VERSION 5.7 ;
  NOWIREEXTENSIONATPIN ON ;
  DIVIDERCHAR "/" ;
  BUSBITCHARS "[]" ;
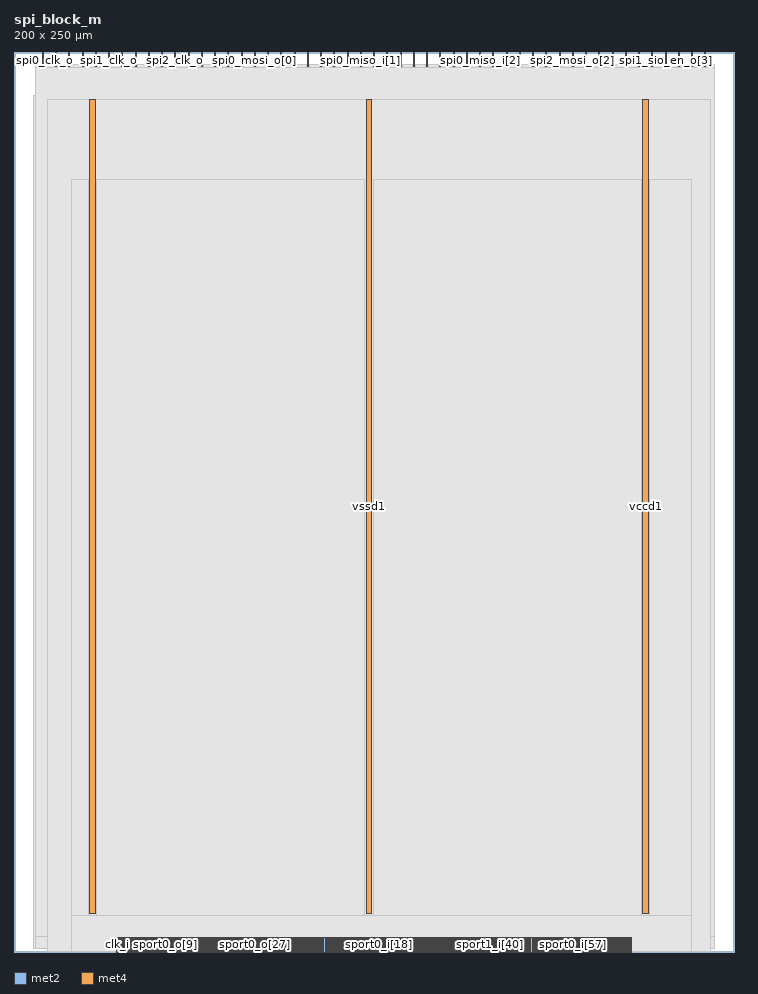
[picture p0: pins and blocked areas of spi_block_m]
MACRO spi_block_m
  CLASS BLOCK ;
  FOREIGN spi_block_m ;
  ORIGIN 0.000 0.000 ;
  SIZE 200.000 BY 250.000 ;
  PIN clk_i
    DIRECTION INPUT ;
    USE SIGNAL ;
    ANTENNAGATEAREA 0.852000 ;
    PORT
      LAYER met2 ;
        RECT 28.610 0.000 28.890 4.000 ;
    END
  END clk_i
  PIN nrst_i
    DIRECTION INPUT ;
    USE SIGNAL ;
    ANTENNAGATEAREA 0.196500 ;
    PORT
      LAYER met2 ;
        RECT 29.070 0.000 29.350 4.000 ;
    END
  END nrst_i
  PIN spi0_clk_o
    DIRECTION OUTPUT TRISTATE ;
    USE SIGNAL ;
    ANTENNADIFFAREA 0.795200 ;
    PORT
      LAYER met2 ;
        RECT 7.910 246.000 8.190 250.000 ;
    END
  END spi0_clk_o
  PIN spi0_cs_o
    DIRECTION OUTPUT TRISTATE ;
    USE SIGNAL ;
    ANTENNADIFFAREA 0.795200 ;
    PORT
      LAYER met2 ;
        RECT 11.590 246.000 11.870 250.000 ;
    END
  END spi0_cs_o
  PIN spi0_dqsm_en_o
    DIRECTION OUTPUT TRISTATE ;
    USE SIGNAL ;
    ANTENNADIFFAREA 0.795200 ;
    PORT
      LAYER met2 ;
        RECT 15.270 246.000 15.550 250.000 ;
    END
  END spi0_dqsm_en_o
  PIN spi0_dqsm_i
    DIRECTION INPUT ;
    USE SIGNAL ;
    ANTENNAGATEAREA 0.196500 ;
    PORT
      LAYER met2 ;
        RECT 18.950 246.000 19.230 250.000 ;
    END
  END spi0_dqsm_i
  PIN spi0_dqsm_o
    DIRECTION OUTPUT TRISTATE ;
    USE SIGNAL ;
    ANTENNADIFFAREA 0.795200 ;
    PORT
      LAYER met2 ;
        RECT 22.630 246.000 22.910 250.000 ;
    END
  END spi0_dqsm_o
  PIN spi0_miso_i[0]
    DIRECTION INPUT ;
    USE SIGNAL ;
    ANTENNAGATEAREA 0.196500 ;
    PORT
      LAYER met2 ;
        RECT 63.110 246.000 63.390 250.000 ;
    END
  END spi0_miso_i[0]
  PIN spi0_miso_i[1]
    DIRECTION INPUT ;
    USE SIGNAL ;
    ANTENNAGATEAREA 0.196500 ;
    PORT
      LAYER met2 ;
        RECT 96.230 246.000 96.510 250.000 ;
    END
  END spi0_miso_i[1]
  PIN spi0_miso_i[2]
    DIRECTION INPUT ;
    USE SIGNAL ;
    ANTENNAGATEAREA 0.196500 ;
    PORT
      LAYER met2 ;
        RECT 129.350 246.000 129.630 250.000 ;
    END
  END spi0_miso_i[2]
  PIN spi0_miso_i[3]
    DIRECTION INPUT ;
    USE SIGNAL ;
    ANTENNAGATEAREA 0.196500 ;
    PORT
      LAYER met2 ;
        RECT 162.470 246.000 162.750 250.000 ;
    END
  END spi0_miso_i[3]
  PIN spi0_mosi_o[0]
    DIRECTION OUTPUT TRISTATE ;
    USE SIGNAL ;
    ANTENNADIFFAREA 0.795200 ;
    PORT
      LAYER met2 ;
        RECT 66.790 246.000 67.070 250.000 ;
    END
  END spi0_mosi_o[0]
  PIN spi0_mosi_o[1]
    DIRECTION OUTPUT TRISTATE ;
    USE SIGNAL ;
    ANTENNADIFFAREA 0.795200 ;
    PORT
      LAYER met2 ;
        RECT 99.910 246.000 100.190 250.000 ;
    END
  END spi0_mosi_o[1]
  PIN spi0_mosi_o[2]
    DIRECTION OUTPUT TRISTATE ;
    USE SIGNAL ;
    ANTENNADIFFAREA 0.795200 ;
    PORT
      LAYER met2 ;
        RECT 133.030 246.000 133.310 250.000 ;
    END
  END spi0_mosi_o[2]
  PIN spi0_mosi_o[3]
    DIRECTION OUTPUT TRISTATE ;
    USE SIGNAL ;
    ANTENNADIFFAREA 0.795200 ;
    PORT
      LAYER met2 ;
        RECT 166.150 246.000 166.430 250.000 ;
    END
  END spi0_mosi_o[3]
  PIN spi0_sio_en_o[0]
    DIRECTION OUTPUT TRISTATE ;
    USE SIGNAL ;
    ANTENNADIFFAREA 0.795200 ;
    PORT
      LAYER met2 ;
        RECT 70.470 246.000 70.750 250.000 ;
    END
  END spi0_sio_en_o[0]
  PIN spi0_sio_en_o[1]
    DIRECTION OUTPUT TRISTATE ;
    USE SIGNAL ;
    ANTENNADIFFAREA 0.795200 ;
    PORT
      LAYER met2 ;
        RECT 103.590 246.000 103.870 250.000 ;
    END
  END spi0_sio_en_o[1]
  PIN spi0_sio_en_o[2]
    DIRECTION OUTPUT TRISTATE ;
    USE SIGNAL ;
    ANTENNADIFFAREA 0.795200 ;
    PORT
      LAYER met2 ;
        RECT 136.710 246.000 136.990 250.000 ;
    END
  END spi0_sio_en_o[2]
  PIN spi0_sio_en_o[3]
    DIRECTION OUTPUT TRISTATE ;
    USE SIGNAL ;
    ANTENNADIFFAREA 0.795200 ;
    PORT
      LAYER met2 ;
        RECT 169.830 246.000 170.110 250.000 ;
    END
  END spi0_sio_en_o[3]
  PIN spi1_clk_o
    DIRECTION OUTPUT TRISTATE ;
    USE SIGNAL ;
    ANTENNADIFFAREA 0.795200 ;
    PORT
      LAYER met2 ;
        RECT 26.310 246.000 26.590 250.000 ;
    END
  END spi1_clk_o
  PIN spi1_cs_o
    DIRECTION OUTPUT TRISTATE ;
    USE SIGNAL ;
    ANTENNADIFFAREA 0.795200 ;
    PORT
      LAYER met2 ;
        RECT 29.990 246.000 30.270 250.000 ;
    END
  END spi1_cs_o
  PIN spi1_dqsm_en_o
    DIRECTION OUTPUT TRISTATE ;
    USE SIGNAL ;
    ANTENNADIFFAREA 0.795200 ;
    PORT
      LAYER met2 ;
        RECT 33.670 246.000 33.950 250.000 ;
    END
  END spi1_dqsm_en_o
  PIN spi1_dqsm_i
    DIRECTION INPUT ;
    USE SIGNAL ;
    ANTENNAGATEAREA 0.196500 ;
    PORT
      LAYER met2 ;
        RECT 37.350 246.000 37.630 250.000 ;
    END
  END spi1_dqsm_i
  PIN spi1_dqsm_o
    DIRECTION OUTPUT TRISTATE ;
    USE SIGNAL ;
    ANTENNADIFFAREA 0.795200 ;
    PORT
      LAYER met2 ;
        RECT 41.030 246.000 41.310 250.000 ;
    END
  END spi1_dqsm_o
  PIN spi1_miso_i[0]
    DIRECTION INPUT ;
    USE SIGNAL ;
    ANTENNAGATEAREA 0.196500 ;
    PORT
      LAYER met2 ;
        RECT 74.150 246.000 74.430 250.000 ;
    END
  END spi1_miso_i[0]
  PIN spi1_miso_i[1]
    DIRECTION INPUT ;
    USE SIGNAL ;
    ANTENNAGATEAREA 0.196500 ;
    PORT
      LAYER met2 ;
        RECT 107.270 246.000 107.550 250.000 ;
    END
  END spi1_miso_i[1]
  PIN spi1_miso_i[2]
    DIRECTION INPUT ;
    USE SIGNAL ;
    ANTENNAGATEAREA 0.196500 ;
    PORT
      LAYER met2 ;
        RECT 140.390 246.000 140.670 250.000 ;
    END
  END spi1_miso_i[2]
  PIN spi1_miso_i[3]
    DIRECTION INPUT ;
    USE SIGNAL ;
    ANTENNAGATEAREA 0.196500 ;
    PORT
      LAYER met2 ;
        RECT 173.510 246.000 173.790 250.000 ;
    END
  END spi1_miso_i[3]
  PIN spi1_mosi_o[0]
    DIRECTION OUTPUT TRISTATE ;
    USE SIGNAL ;
    ANTENNADIFFAREA 0.795200 ;
    PORT
      LAYER met2 ;
        RECT 77.830 246.000 78.110 250.000 ;
    END
  END spi1_mosi_o[0]
  PIN spi1_mosi_o[1]
    DIRECTION OUTPUT TRISTATE ;
    USE SIGNAL ;
    ANTENNADIFFAREA 0.795200 ;
    PORT
      LAYER met2 ;
        RECT 110.950 246.000 111.230 250.000 ;
    END
  END spi1_mosi_o[1]
  PIN spi1_mosi_o[2]
    DIRECTION OUTPUT TRISTATE ;
    USE SIGNAL ;
    ANTENNADIFFAREA 0.795200 ;
    PORT
      LAYER met2 ;
        RECT 144.070 246.000 144.350 250.000 ;
    END
  END spi1_mosi_o[2]
  PIN spi1_mosi_o[3]
    DIRECTION OUTPUT TRISTATE ;
    USE SIGNAL ;
    ANTENNADIFFAREA 0.795200 ;
    PORT
      LAYER met2 ;
        RECT 177.190 246.000 177.470 250.000 ;
    END
  END spi1_mosi_o[3]
  PIN spi1_sio_en_o[0]
    DIRECTION OUTPUT TRISTATE ;
    USE SIGNAL ;
    ANTENNADIFFAREA 0.795200 ;
    PORT
      LAYER met2 ;
        RECT 81.510 246.000 81.790 250.000 ;
    END
  END spi1_sio_en_o[0]
  PIN spi1_sio_en_o[1]
    DIRECTION OUTPUT TRISTATE ;
    USE SIGNAL ;
    ANTENNADIFFAREA 0.795200 ;
    PORT
      LAYER met2 ;
        RECT 114.630 246.000 114.910 250.000 ;
    END
  END spi1_sio_en_o[1]
  PIN spi1_sio_en_o[2]
    DIRECTION OUTPUT TRISTATE ;
    USE SIGNAL ;
    ANTENNADIFFAREA 0.795200 ;
    PORT
      LAYER met2 ;
        RECT 147.750 246.000 148.030 250.000 ;
    END
  END spi1_sio_en_o[2]
  PIN spi1_sio_en_o[3]
    DIRECTION OUTPUT TRISTATE ;
    USE SIGNAL ;
    ANTENNADIFFAREA 0.795200 ;
    PORT
      LAYER met2 ;
        RECT 180.870 246.000 181.150 250.000 ;
    END
  END spi1_sio_en_o[3]
  PIN spi2_clk_o
    DIRECTION OUTPUT TRISTATE ;
    USE SIGNAL ;
    ANTENNADIFFAREA 0.795200 ;
    PORT
      LAYER met2 ;
        RECT 44.710 246.000 44.990 250.000 ;
    END
  END spi2_clk_o
  PIN spi2_cs_o
    DIRECTION OUTPUT TRISTATE ;
    USE SIGNAL ;
    ANTENNADIFFAREA 0.795200 ;
    PORT
      LAYER met2 ;
        RECT 48.390 246.000 48.670 250.000 ;
    END
  END spi2_cs_o
  PIN spi2_dqsm_en_o
    DIRECTION OUTPUT TRISTATE ;
    USE SIGNAL ;
    ANTENNADIFFAREA 0.795200 ;
    PORT
      LAYER met2 ;
        RECT 52.070 246.000 52.350 250.000 ;
    END
  END spi2_dqsm_en_o
  PIN spi2_dqsm_i
    DIRECTION INPUT ;
    USE SIGNAL ;
    ANTENNAGATEAREA 0.196500 ;
    PORT
      LAYER met2 ;
        RECT 55.750 246.000 56.030 250.000 ;
    END
  END spi2_dqsm_i
  PIN spi2_dqsm_o
    DIRECTION OUTPUT TRISTATE ;
    USE SIGNAL ;
    ANTENNADIFFAREA 0.795200 ;
    PORT
      LAYER met2 ;
        RECT 59.430 246.000 59.710 250.000 ;
    END
  END spi2_dqsm_o
  PIN spi2_miso_i[0]
    DIRECTION INPUT ;
    USE SIGNAL ;
    ANTENNAGATEAREA 0.196500 ;
    PORT
      LAYER met2 ;
        RECT 85.190 246.000 85.470 250.000 ;
    END
  END spi2_miso_i[0]
  PIN spi2_miso_i[1]
    DIRECTION INPUT ;
    USE SIGNAL ;
    ANTENNAGATEAREA 0.196500 ;
    PORT
      LAYER met2 ;
        RECT 118.310 246.000 118.590 250.000 ;
    END
  END spi2_miso_i[1]
  PIN spi2_miso_i[2]
    DIRECTION INPUT ;
    USE SIGNAL ;
    ANTENNAGATEAREA 0.196500 ;
    PORT
      LAYER met2 ;
        RECT 151.430 246.000 151.710 250.000 ;
    END
  END spi2_miso_i[2]
  PIN spi2_miso_i[3]
    DIRECTION INPUT ;
    USE SIGNAL ;
    ANTENNAGATEAREA 0.196500 ;
    PORT
      LAYER met2 ;
        RECT 184.550 246.000 184.830 250.000 ;
    END
  END spi2_miso_i[3]
  PIN spi2_mosi_o[0]
    DIRECTION OUTPUT TRISTATE ;
    USE SIGNAL ;
    ANTENNADIFFAREA 0.795200 ;
    PORT
      LAYER met2 ;
        RECT 88.870 246.000 89.150 250.000 ;
    END
  END spi2_mosi_o[0]
  PIN spi2_mosi_o[1]
    DIRECTION OUTPUT TRISTATE ;
    USE SIGNAL ;
    ANTENNADIFFAREA 0.795200 ;
    PORT
      LAYER met2 ;
        RECT 121.990 246.000 122.270 250.000 ;
    END
  END spi2_mosi_o[1]
  PIN spi2_mosi_o[2]
    DIRECTION OUTPUT TRISTATE ;
    USE SIGNAL ;
    ANTENNADIFFAREA 0.795200 ;
    PORT
      LAYER met2 ;
        RECT 155.110 246.000 155.390 250.000 ;
    END
  END spi2_mosi_o[2]
  PIN spi2_mosi_o[3]
    DIRECTION OUTPUT TRISTATE ;
    USE SIGNAL ;
    ANTENNADIFFAREA 0.795200 ;
    PORT
      LAYER met2 ;
        RECT 188.230 246.000 188.510 250.000 ;
    END
  END spi2_mosi_o[3]
  PIN spi2_sio_en_o[0]
    DIRECTION OUTPUT TRISTATE ;
    USE SIGNAL ;
    ANTENNADIFFAREA 0.795200 ;
    PORT
      LAYER met2 ;
        RECT 92.550 246.000 92.830 250.000 ;
    END
  END spi2_sio_en_o[0]
  PIN spi2_sio_en_o[1]
    DIRECTION OUTPUT TRISTATE ;
    USE SIGNAL ;
    ANTENNADIFFAREA 0.795200 ;
    PORT
      LAYER met2 ;
        RECT 125.670 246.000 125.950 250.000 ;
    END
  END spi2_sio_en_o[1]
  PIN spi2_sio_en_o[2]
    DIRECTION OUTPUT TRISTATE ;
    USE SIGNAL ;
    ANTENNADIFFAREA 0.795200 ;
    PORT
      LAYER met2 ;
        RECT 158.790 246.000 159.070 250.000 ;
    END
  END spi2_sio_en_o[2]
  PIN spi2_sio_en_o[3]
    DIRECTION OUTPUT TRISTATE ;
    USE SIGNAL ;
    ANTENNADIFFAREA 0.795200 ;
    PORT
      LAYER met2 ;
        RECT 191.910 246.000 192.190 250.000 ;
    END
  END spi2_sio_en_o[3]
  PIN sport0_i[0]
    DIRECTION INPUT ;
    USE SIGNAL ;
    ANTENNAGATEAREA 0.196500 ;
    PORT
      LAYER met2 ;
        RECT 76.450 0.000 76.730 4.000 ;
    END
  END sport0_i[0]
  PIN sport0_i[10]
    DIRECTION INPUT ;
    USE SIGNAL ;
    ANTENNAGATEAREA 0.196500 ;
    PORT
      LAYER met2 ;
        RECT 90.250 0.000 90.530 4.000 ;
    END
  END sport0_i[10]
  PIN sport0_i[11]
    DIRECTION INPUT ;
    USE SIGNAL ;
    ANTENNAGATEAREA 0.196500 ;
    PORT
      LAYER met2 ;
        RECT 91.630 0.000 91.910 4.000 ;
    END
  END sport0_i[11]
  PIN sport0_i[12]
    DIRECTION INPUT ;
    USE SIGNAL ;
    ANTENNAGATEAREA 0.196500 ;
    PORT
      LAYER met2 ;
        RECT 93.010 0.000 93.290 4.000 ;
    END
  END sport0_i[12]
  PIN sport0_i[13]
    DIRECTION INPUT ;
    USE SIGNAL ;
    ANTENNAGATEAREA 0.196500 ;
    PORT
      LAYER met2 ;
        RECT 94.390 0.000 94.670 4.000 ;
    END
  END sport0_i[13]
  PIN sport0_i[14]
    DIRECTION INPUT ;
    USE SIGNAL ;
    ANTENNAGATEAREA 0.196500 ;
    PORT
      LAYER met2 ;
        RECT 95.770 0.000 96.050 4.000 ;
    END
  END sport0_i[14]
  PIN sport0_i[15]
    DIRECTION INPUT ;
    USE SIGNAL ;
    ANTENNAGATEAREA 0.196500 ;
    PORT
      LAYER met2 ;
        RECT 97.150 0.000 97.430 4.000 ;
    END
  END sport0_i[15]
  PIN sport0_i[16]
    DIRECTION INPUT ;
    USE SIGNAL ;
    ANTENNAGATEAREA 0.196500 ;
    PORT
      LAYER met2 ;
        RECT 98.530 0.000 98.810 4.000 ;
    END
  END sport0_i[16]
  PIN sport0_i[17]
    DIRECTION INPUT ;
    USE SIGNAL ;
    ANTENNAGATEAREA 0.196500 ;
    PORT
      LAYER met2 ;
        RECT 99.910 0.000 100.190 4.000 ;
    END
  END sport0_i[17]
  PIN sport0_i[18]
    DIRECTION INPUT ;
    USE SIGNAL ;
    ANTENNAGATEAREA 0.196500 ;
    PORT
      LAYER met2 ;
        RECT 101.290 0.000 101.570 4.000 ;
    END
  END sport0_i[18]
  PIN sport0_i[19]
    DIRECTION INPUT ;
    USE SIGNAL ;
    ANTENNAGATEAREA 0.196500 ;
    PORT
      LAYER met2 ;
        RECT 102.670 0.000 102.950 4.000 ;
    END
  END sport0_i[19]
  PIN sport0_i[1]
    DIRECTION INPUT ;
    USE SIGNAL ;
    ANTENNAGATEAREA 0.196500 ;
    ANTENNADIFFAREA 0.434700 ;
    PORT
      LAYER met2 ;
        RECT 77.830 0.000 78.110 4.000 ;
    END
  END sport0_i[1]
  PIN sport0_i[20]
    DIRECTION INPUT ;
    USE SIGNAL ;
    ANTENNAGATEAREA 0.196500 ;
    PORT
      LAYER met2 ;
        RECT 104.050 0.000 104.330 4.000 ;
    END
  END sport0_i[20]
  PIN sport0_i[21]
    DIRECTION INPUT ;
    USE SIGNAL ;
    ANTENNAGATEAREA 0.196500 ;
    PORT
      LAYER met2 ;
        RECT 105.430 0.000 105.710 4.000 ;
    END
  END sport0_i[21]
  PIN sport0_i[22]
    DIRECTION INPUT ;
    USE SIGNAL ;
    ANTENNAGATEAREA 0.196500 ;
    PORT
      LAYER met2 ;
        RECT 106.810 0.000 107.090 4.000 ;
    END
  END sport0_i[22]
  PIN sport0_i[23]
    DIRECTION INPUT ;
    USE SIGNAL ;
    ANTENNAGATEAREA 0.196500 ;
    PORT
      LAYER met2 ;
        RECT 108.190 0.000 108.470 4.000 ;
    END
  END sport0_i[23]
  PIN sport0_i[24]
    DIRECTION INPUT ;
    USE SIGNAL ;
    ANTENNAGATEAREA 0.196500 ;
    PORT
      LAYER met2 ;
        RECT 109.570 0.000 109.850 4.000 ;
    END
  END sport0_i[24]
  PIN sport0_i[25]
    DIRECTION INPUT ;
    USE SIGNAL ;
    ANTENNAGATEAREA 0.196500 ;
    PORT
      LAYER met2 ;
        RECT 110.950 0.000 111.230 4.000 ;
    END
  END sport0_i[25]
  PIN sport0_i[26]
    DIRECTION INPUT ;
    USE SIGNAL ;
    ANTENNAGATEAREA 0.196500 ;
    PORT
      LAYER met2 ;
        RECT 112.330 0.000 112.610 4.000 ;
    END
  END sport0_i[26]
  PIN sport0_i[27]
    DIRECTION INPUT ;
    USE SIGNAL ;
    ANTENNAGATEAREA 0.196500 ;
    PORT
      LAYER met2 ;
        RECT 113.710 0.000 113.990 4.000 ;
    END
  END sport0_i[27]
  PIN sport0_i[28]
    DIRECTION INPUT ;
    USE SIGNAL ;
    ANTENNAGATEAREA 0.196500 ;
    PORT
      LAYER met2 ;
        RECT 115.090 0.000 115.370 4.000 ;
    END
  END sport0_i[28]
  PIN sport0_i[29]
    DIRECTION INPUT ;
    USE SIGNAL ;
    ANTENNAGATEAREA 0.196500 ;
    PORT
      LAYER met2 ;
        RECT 116.470 0.000 116.750 4.000 ;
    END
  END sport0_i[29]
  PIN sport0_i[2]
    DIRECTION INPUT ;
    USE SIGNAL ;
    ANTENNAGATEAREA 0.196500 ;
    PORT
      LAYER met2 ;
        RECT 79.210 0.000 79.490 4.000 ;
    END
  END sport0_i[2]
  PIN sport0_i[30]
    DIRECTION INPUT ;
    USE SIGNAL ;
    ANTENNAGATEAREA 0.196500 ;
    PORT
      LAYER met2 ;
        RECT 117.850 0.000 118.130 4.000 ;
    END
  END sport0_i[30]
  PIN sport0_i[31]
    DIRECTION INPUT ;
    USE SIGNAL ;
    ANTENNAGATEAREA 0.196500 ;
    PORT
      LAYER met2 ;
        RECT 119.230 0.000 119.510 4.000 ;
    END
  END sport0_i[31]
  PIN sport0_i[32]
    DIRECTION INPUT ;
    USE SIGNAL ;
    ANTENNAGATEAREA 0.196500 ;
    PORT
      LAYER met2 ;
        RECT 120.610 0.000 120.890 4.000 ;
    END
  END sport0_i[32]
  PIN sport0_i[33]
    DIRECTION INPUT ;
    USE SIGNAL ;
    ANTENNAGATEAREA 0.196500 ;
    PORT
      LAYER met2 ;
        RECT 121.990 0.000 122.270 4.000 ;
    END
  END sport0_i[33]
  PIN sport0_i[34]
    DIRECTION INPUT ;
    USE SIGNAL ;
    ANTENNAGATEAREA 0.196500 ;
    PORT
      LAYER met2 ;
        RECT 123.370 0.000 123.650 4.000 ;
    END
  END sport0_i[34]
  PIN sport0_i[35]
    DIRECTION INPUT ;
    USE SIGNAL ;
    ANTENNAGATEAREA 0.196500 ;
    PORT
      LAYER met2 ;
        RECT 124.750 0.000 125.030 4.000 ;
    END
  END sport0_i[35]
  PIN sport0_i[36]
    DIRECTION INPUT ;
    USE SIGNAL ;
    ANTENNAGATEAREA 0.196500 ;
    PORT
      LAYER met2 ;
        RECT 126.130 0.000 126.410 4.000 ;
    END
  END sport0_i[36]
  PIN sport0_i[37]
    DIRECTION INPUT ;
    USE SIGNAL ;
    ANTENNAGATEAREA 0.196500 ;
    PORT
      LAYER met2 ;
        RECT 127.510 0.000 127.790 4.000 ;
    END
  END sport0_i[37]
  PIN sport0_i[38]
    DIRECTION INPUT ;
    USE SIGNAL ;
    ANTENNAGATEAREA 0.196500 ;
    PORT
      LAYER met2 ;
        RECT 128.890 0.000 129.170 4.000 ;
    END
  END sport0_i[38]
  PIN sport0_i[39]
    DIRECTION INPUT ;
    USE SIGNAL ;
    ANTENNAGATEAREA 0.196500 ;
    PORT
      LAYER met2 ;
        RECT 130.270 0.000 130.550 4.000 ;
    END
  END sport0_i[39]
  PIN sport0_i[3]
    DIRECTION INPUT ;
    USE SIGNAL ;
    ANTENNAGATEAREA 0.196500 ;
    PORT
      LAYER met2 ;
        RECT 80.590 0.000 80.870 4.000 ;
    END
  END sport0_i[3]
  PIN sport0_i[40]
    DIRECTION INPUT ;
    USE SIGNAL ;
    ANTENNAGATEAREA 0.196500 ;
    PORT
      LAYER met2 ;
        RECT 131.650 0.000 131.930 4.000 ;
    END
  END sport0_i[40]
  PIN sport0_i[41]
    DIRECTION INPUT ;
    USE SIGNAL ;
    ANTENNAGATEAREA 0.196500 ;
    PORT
      LAYER met2 ;
        RECT 133.030 0.000 133.310 4.000 ;
    END
  END sport0_i[41]
  PIN sport0_i[42]
    DIRECTION INPUT ;
    USE SIGNAL ;
    ANTENNAGATEAREA 0.196500 ;
    PORT
      LAYER met2 ;
        RECT 134.410 0.000 134.690 4.000 ;
    END
  END sport0_i[42]
  PIN sport0_i[43]
    DIRECTION INPUT ;
    USE SIGNAL ;
    ANTENNAGATEAREA 0.196500 ;
    PORT
      LAYER met2 ;
        RECT 135.790 0.000 136.070 4.000 ;
    END
  END sport0_i[43]
  PIN sport0_i[44]
    DIRECTION INPUT ;
    USE SIGNAL ;
    ANTENNAGATEAREA 0.196500 ;
    PORT
      LAYER met2 ;
        RECT 137.170 0.000 137.450 4.000 ;
    END
  END sport0_i[44]
  PIN sport0_i[45]
    DIRECTION INPUT ;
    USE SIGNAL ;
    ANTENNAGATEAREA 0.196500 ;
    PORT
      LAYER met2 ;
        RECT 138.550 0.000 138.830 4.000 ;
    END
  END sport0_i[45]
  PIN sport0_i[46]
    DIRECTION INPUT ;
    USE SIGNAL ;
    ANTENNAGATEAREA 0.196500 ;
    PORT
      LAYER met2 ;
        RECT 139.930 0.000 140.210 4.000 ;
    END
  END sport0_i[46]
  PIN sport0_i[47]
    DIRECTION INPUT ;
    USE SIGNAL ;
    ANTENNAGATEAREA 0.196500 ;
    PORT
      LAYER met2 ;
        RECT 141.310 0.000 141.590 4.000 ;
    END
  END sport0_i[47]
  PIN sport0_i[48]
    DIRECTION INPUT ;
    USE SIGNAL ;
    ANTENNAGATEAREA 0.196500 ;
    PORT
      LAYER met2 ;
        RECT 142.690 0.000 142.970 4.000 ;
    END
  END sport0_i[48]
  PIN sport0_i[49]
    DIRECTION INPUT ;
    USE SIGNAL ;
    ANTENNAGATEAREA 0.196500 ;
    PORT
      LAYER met2 ;
        RECT 144.070 0.000 144.350 4.000 ;
    END
  END sport0_i[49]
  PIN sport0_i[4]
    DIRECTION INPUT ;
    USE SIGNAL ;
    ANTENNAGATEAREA 0.213000 ;
    PORT
      LAYER met2 ;
        RECT 81.970 0.000 82.250 4.000 ;
    END
  END sport0_i[4]
  PIN sport0_i[50]
    DIRECTION INPUT ;
    USE SIGNAL ;
    ANTENNAGATEAREA 0.196500 ;
    PORT
      LAYER met2 ;
        RECT 145.450 0.000 145.730 4.000 ;
    END
  END sport0_i[50]
  PIN sport0_i[51]
    DIRECTION INPUT ;
    USE SIGNAL ;
    ANTENNAGATEAREA 0.196500 ;
    PORT
      LAYER met2 ;
        RECT 146.830 0.000 147.110 4.000 ;
    END
  END sport0_i[51]
  PIN sport0_i[52]
    DIRECTION INPUT ;
    USE SIGNAL ;
    ANTENNAGATEAREA 0.196500 ;
    PORT
      LAYER met2 ;
        RECT 148.210 0.000 148.490 4.000 ;
    END
  END sport0_i[52]
  PIN sport0_i[53]
    DIRECTION INPUT ;
    USE SIGNAL ;
    ANTENNAGATEAREA 0.196500 ;
    PORT
      LAYER met2 ;
        RECT 149.590 0.000 149.870 4.000 ;
    END
  END sport0_i[53]
  PIN sport0_i[54]
    DIRECTION INPUT ;
    USE SIGNAL ;
    ANTENNAGATEAREA 0.196500 ;
    PORT
      LAYER met2 ;
        RECT 150.970 0.000 151.250 4.000 ;
    END
  END sport0_i[54]
  PIN sport0_i[55]
    DIRECTION INPUT ;
    USE SIGNAL ;
    ANTENNAGATEAREA 0.196500 ;
    PORT
      LAYER met2 ;
        RECT 152.350 0.000 152.630 4.000 ;
    END
  END sport0_i[55]
  PIN sport0_i[56]
    DIRECTION INPUT ;
    USE SIGNAL ;
    ANTENNAGATEAREA 0.196500 ;
    PORT
      LAYER met2 ;
        RECT 153.730 0.000 154.010 4.000 ;
    END
  END sport0_i[56]
  PIN sport0_i[57]
    DIRECTION INPUT ;
    USE SIGNAL ;
    ANTENNAGATEAREA 0.196500 ;
    PORT
      LAYER met2 ;
        RECT 155.110 0.000 155.390 4.000 ;
    END
  END sport0_i[57]
  PIN sport0_i[58]
    DIRECTION INPUT ;
    USE SIGNAL ;
    ANTENNAGATEAREA 0.196500 ;
    PORT
      LAYER met2 ;
        RECT 156.490 0.000 156.770 4.000 ;
    END
  END sport0_i[58]
  PIN sport0_i[59]
    DIRECTION INPUT ;
    USE SIGNAL ;
    ANTENNAGATEAREA 0.196500 ;
    PORT
      LAYER met2 ;
        RECT 157.870 0.000 158.150 4.000 ;
    END
  END sport0_i[59]
  PIN sport0_i[5]
    DIRECTION INPUT ;
    USE SIGNAL ;
    ANTENNAGATEAREA 0.213000 ;
    PORT
      LAYER met2 ;
        RECT 83.350 0.000 83.630 4.000 ;
    END
  END sport0_i[5]
  PIN sport0_i[60]
    DIRECTION INPUT ;
    USE SIGNAL ;
    ANTENNAGATEAREA 0.196500 ;
    PORT
      LAYER met2 ;
        RECT 159.250 0.000 159.530 4.000 ;
    END
  END sport0_i[60]
  PIN sport0_i[61]
    DIRECTION INPUT ;
    USE SIGNAL ;
    ANTENNAGATEAREA 0.196500 ;
    PORT
      LAYER met2 ;
        RECT 160.630 0.000 160.910 4.000 ;
    END
  END sport0_i[61]
  PIN sport0_i[62]
    DIRECTION INPUT ;
    USE SIGNAL ;
    ANTENNAGATEAREA 0.196500 ;
    PORT
      LAYER met2 ;
        RECT 162.010 0.000 162.290 4.000 ;
    END
  END sport0_i[62]
  PIN sport0_i[63]
    DIRECTION INPUT ;
    USE SIGNAL ;
    ANTENNAGATEAREA 0.196500 ;
    PORT
      LAYER met2 ;
        RECT 163.390 0.000 163.670 4.000 ;
    END
  END sport0_i[63]
  PIN sport0_i[64]
    DIRECTION INPUT ;
    USE SIGNAL ;
    ANTENNAGATEAREA 0.126000 ;
    PORT
      LAYER met2 ;
        RECT 164.770 0.000 165.050 4.000 ;
    END
  END sport0_i[64]
  PIN sport0_i[65]
    DIRECTION INPUT ;
    USE SIGNAL ;
    ANTENNAGATEAREA 0.126000 ;
    PORT
      LAYER met2 ;
        RECT 166.150 0.000 166.430 4.000 ;
    END
  END sport0_i[65]
  PIN sport0_i[66]
    DIRECTION INPUT ;
    USE SIGNAL ;
    ANTENNAGATEAREA 0.213000 ;
    PORT
      LAYER met2 ;
        RECT 167.530 0.000 167.810 4.000 ;
    END
  END sport0_i[66]
  PIN sport0_i[67]
    DIRECTION INPUT ;
    USE SIGNAL ;
    ANTENNAGATEAREA 0.213000 ;
    PORT
      LAYER met2 ;
        RECT 168.910 0.000 169.190 4.000 ;
    END
  END sport0_i[67]
  PIN sport0_i[68]
    DIRECTION INPUT ;
    USE SIGNAL ;
    ANTENNAGATEAREA 0.213000 ;
    PORT
      LAYER met2 ;
        RECT 170.290 0.000 170.570 4.000 ;
    END
  END sport0_i[68]
  PIN sport0_i[6]
    DIRECTION INPUT ;
    USE SIGNAL ;
    ANTENNAGATEAREA 0.126000 ;
    PORT
      LAYER met2 ;
        RECT 84.730 0.000 85.010 4.000 ;
    END
  END sport0_i[6]
  PIN sport0_i[7]
    DIRECTION INPUT ;
    USE SIGNAL ;
    ANTENNAGATEAREA 0.213000 ;
    PORT
      LAYER met2 ;
        RECT 86.110 0.000 86.390 4.000 ;
    END
  END sport0_i[7]
  PIN sport0_i[8]
    DIRECTION INPUT ;
    USE SIGNAL ;
    ANTENNAGATEAREA 0.196500 ;
    PORT
      LAYER met2 ;
        RECT 87.490 0.000 87.770 4.000 ;
    END
  END sport0_i[8]
  PIN sport0_i[9]
    DIRECTION INPUT ;
    USE SIGNAL ;
    ANTENNAGATEAREA 0.196500 ;
    PORT
      LAYER met2 ;
        RECT 88.870 0.000 89.150 4.000 ;
    END
  END sport0_i[9]
  PIN sport0_o[0]
    DIRECTION OUTPUT TRISTATE ;
    USE SIGNAL ;
    ANTENNADIFFAREA 0.795200 ;
    PORT
      LAYER met2 ;
        RECT 29.530 0.000 29.810 4.000 ;
    END
  END sport0_o[0]
  PIN sport0_o[10]
    DIRECTION OUTPUT TRISTATE ;
    USE SIGNAL ;
    ANTENNADIFFAREA 0.795200 ;
    PORT
      LAYER met2 ;
        RECT 43.330 0.000 43.610 4.000 ;
    END
  END sport0_o[10]
  PIN sport0_o[11]
    DIRECTION OUTPUT TRISTATE ;
    USE SIGNAL ;
    ANTENNADIFFAREA 0.795200 ;
    PORT
      LAYER met2 ;
        RECT 44.710 0.000 44.990 4.000 ;
    END
  END sport0_o[11]
  PIN sport0_o[12]
    DIRECTION OUTPUT TRISTATE ;
    USE SIGNAL ;
    ANTENNADIFFAREA 0.795200 ;
    PORT
      LAYER met2 ;
        RECT 46.090 0.000 46.370 4.000 ;
    END
  END sport0_o[12]
  PIN sport0_o[13]
    DIRECTION OUTPUT TRISTATE ;
    USE SIGNAL ;
    ANTENNADIFFAREA 0.795200 ;
    PORT
      LAYER met2 ;
        RECT 47.470 0.000 47.750 4.000 ;
    END
  END sport0_o[13]
  PIN sport0_o[14]
    DIRECTION OUTPUT TRISTATE ;
    USE SIGNAL ;
    ANTENNADIFFAREA 0.795200 ;
    PORT
      LAYER met2 ;
        RECT 48.850 0.000 49.130 4.000 ;
    END
  END sport0_o[14]
  PIN sport0_o[15]
    DIRECTION OUTPUT TRISTATE ;
    USE SIGNAL ;
    ANTENNADIFFAREA 0.795200 ;
    PORT
      LAYER met2 ;
        RECT 50.230 0.000 50.510 4.000 ;
    END
  END sport0_o[15]
  PIN sport0_o[16]
    DIRECTION OUTPUT TRISTATE ;
    USE SIGNAL ;
    ANTENNADIFFAREA 0.795200 ;
    PORT
      LAYER met2 ;
        RECT 51.610 0.000 51.890 4.000 ;
    END
  END sport0_o[16]
  PIN sport0_o[17]
    DIRECTION OUTPUT TRISTATE ;
    USE SIGNAL ;
    ANTENNADIFFAREA 0.795200 ;
    PORT
      LAYER met2 ;
        RECT 52.990 0.000 53.270 4.000 ;
    END
  END sport0_o[17]
  PIN sport0_o[18]
    DIRECTION OUTPUT TRISTATE ;
    USE SIGNAL ;
    ANTENNADIFFAREA 0.795200 ;
    PORT
      LAYER met2 ;
        RECT 54.370 0.000 54.650 4.000 ;
    END
  END sport0_o[18]
  PIN sport0_o[19]
    DIRECTION OUTPUT TRISTATE ;
    USE SIGNAL ;
    ANTENNADIFFAREA 0.795200 ;
    PORT
      LAYER met2 ;
        RECT 55.750 0.000 56.030 4.000 ;
    END
  END sport0_o[19]
  PIN sport0_o[1]
    DIRECTION OUTPUT TRISTATE ;
    USE SIGNAL ;
    ANTENNADIFFAREA 0.795200 ;
    PORT
      LAYER met2 ;
        RECT 30.910 0.000 31.190 4.000 ;
    END
  END sport0_o[1]
  PIN sport0_o[20]
    DIRECTION OUTPUT TRISTATE ;
    USE SIGNAL ;
    ANTENNADIFFAREA 0.795200 ;
    PORT
      LAYER met2 ;
        RECT 57.130 0.000 57.410 4.000 ;
    END
  END sport0_o[20]
  PIN sport0_o[21]
    DIRECTION OUTPUT TRISTATE ;
    USE SIGNAL ;
    ANTENNADIFFAREA 0.795200 ;
    PORT
      LAYER met2 ;
        RECT 58.510 0.000 58.790 4.000 ;
    END
  END sport0_o[21]
  PIN sport0_o[22]
    DIRECTION OUTPUT TRISTATE ;
    USE SIGNAL ;
    ANTENNADIFFAREA 0.795200 ;
    PORT
      LAYER met2 ;
        RECT 59.890 0.000 60.170 4.000 ;
    END
  END sport0_o[22]
  PIN sport0_o[23]
    DIRECTION OUTPUT TRISTATE ;
    USE SIGNAL ;
    ANTENNADIFFAREA 0.795200 ;
    PORT
      LAYER met2 ;
        RECT 61.270 0.000 61.550 4.000 ;
    END
  END sport0_o[23]
  PIN sport0_o[24]
    DIRECTION OUTPUT TRISTATE ;
    USE SIGNAL ;
    ANTENNADIFFAREA 0.795200 ;
    PORT
      LAYER met2 ;
        RECT 62.650 0.000 62.930 4.000 ;
    END
  END sport0_o[24]
  PIN sport0_o[25]
    DIRECTION OUTPUT TRISTATE ;
    USE SIGNAL ;
    ANTENNADIFFAREA 0.795200 ;
    PORT
      LAYER met2 ;
        RECT 64.030 0.000 64.310 4.000 ;
    END
  END sport0_o[25]
  PIN sport0_o[26]
    DIRECTION OUTPUT TRISTATE ;
    USE SIGNAL ;
    ANTENNADIFFAREA 0.795200 ;
    PORT
      LAYER met2 ;
        RECT 65.410 0.000 65.690 4.000 ;
    END
  END sport0_o[26]
  PIN sport0_o[27]
    DIRECTION OUTPUT TRISTATE ;
    USE SIGNAL ;
    ANTENNADIFFAREA 0.795200 ;
    PORT
      LAYER met2 ;
        RECT 66.790 0.000 67.070 4.000 ;
    END
  END sport0_o[27]
  PIN sport0_o[28]
    DIRECTION OUTPUT TRISTATE ;
    USE SIGNAL ;
    ANTENNADIFFAREA 0.795200 ;
    PORT
      LAYER met2 ;
        RECT 68.170 0.000 68.450 4.000 ;
    END
  END sport0_o[28]
  PIN sport0_o[29]
    DIRECTION OUTPUT TRISTATE ;
    USE SIGNAL ;
    ANTENNADIFFAREA 0.795200 ;
    PORT
      LAYER met2 ;
        RECT 69.550 0.000 69.830 4.000 ;
    END
  END sport0_o[29]
  PIN sport0_o[2]
    DIRECTION OUTPUT TRISTATE ;
    USE SIGNAL ;
    ANTENNADIFFAREA 0.795200 ;
    PORT
      LAYER met2 ;
        RECT 32.290 0.000 32.570 4.000 ;
    END
  END sport0_o[2]
  PIN sport0_o[30]
    DIRECTION OUTPUT TRISTATE ;
    USE SIGNAL ;
    ANTENNADIFFAREA 0.795200 ;
    PORT
      LAYER met2 ;
        RECT 70.930 0.000 71.210 4.000 ;
    END
  END sport0_o[30]
  PIN sport0_o[31]
    DIRECTION OUTPUT TRISTATE ;
    USE SIGNAL ;
    ANTENNADIFFAREA 0.795200 ;
    PORT
      LAYER met2 ;
        RECT 72.310 0.000 72.590 4.000 ;
    END
  END sport0_o[31]
  PIN sport0_o[32]
    DIRECTION OUTPUT TRISTATE ;
    USE SIGNAL ;
    ANTENNADIFFAREA 0.795200 ;
    PORT
      LAYER met2 ;
        RECT 73.690 0.000 73.970 4.000 ;
    END
  END sport0_o[32]
  PIN sport0_o[33]
    DIRECTION OUTPUT TRISTATE ;
    USE SIGNAL ;
    ANTENNADIFFAREA 0.795200 ;
    PORT
      LAYER met2 ;
        RECT 75.070 0.000 75.350 4.000 ;
    END
  END sport0_o[33]
  PIN sport0_o[3]
    DIRECTION OUTPUT TRISTATE ;
    USE SIGNAL ;
    ANTENNADIFFAREA 0.795200 ;
    PORT
      LAYER met2 ;
        RECT 33.670 0.000 33.950 4.000 ;
    END
  END sport0_o[3]
  PIN sport0_o[4]
    DIRECTION OUTPUT TRISTATE ;
    USE SIGNAL ;
    ANTENNADIFFAREA 0.795200 ;
    PORT
      LAYER met2 ;
        RECT 35.050 0.000 35.330 4.000 ;
    END
  END sport0_o[4]
  PIN sport0_o[5]
    DIRECTION OUTPUT TRISTATE ;
    USE SIGNAL ;
    ANTENNADIFFAREA 0.795200 ;
    PORT
      LAYER met2 ;
        RECT 36.430 0.000 36.710 4.000 ;
    END
  END sport0_o[5]
  PIN sport0_o[6]
    DIRECTION OUTPUT TRISTATE ;
    USE SIGNAL ;
    ANTENNADIFFAREA 0.795200 ;
    PORT
      LAYER met2 ;
        RECT 37.810 0.000 38.090 4.000 ;
    END
  END sport0_o[6]
  PIN sport0_o[7]
    DIRECTION OUTPUT TRISTATE ;
    USE SIGNAL ;
    ANTENNADIFFAREA 0.795200 ;
    PORT
      LAYER met2 ;
        RECT 39.190 0.000 39.470 4.000 ;
    END
  END sport0_o[7]
  PIN sport0_o[8]
    DIRECTION OUTPUT TRISTATE ;
    USE SIGNAL ;
    ANTENNADIFFAREA 0.795200 ;
    PORT
      LAYER met2 ;
        RECT 40.570 0.000 40.850 4.000 ;
    END
  END sport0_o[8]
  PIN sport0_o[9]
    DIRECTION OUTPUT TRISTATE ;
    USE SIGNAL ;
    ANTENNADIFFAREA 0.795200 ;
    PORT
      LAYER met2 ;
        RECT 41.950 0.000 42.230 4.000 ;
    END
  END sport0_o[9]
  PIN sport1_i[0]
    DIRECTION INPUT ;
    USE SIGNAL ;
    ANTENNAGATEAREA 0.126000 ;
    PORT
      LAYER met2 ;
        RECT 76.910 0.000 77.190 4.000 ;
    END
  END sport1_i[0]
  PIN sport1_i[10]
    DIRECTION INPUT ;
    USE SIGNAL ;
    ANTENNAGATEAREA 0.126000 ;
    PORT
      LAYER met2 ;
        RECT 90.710 0.000 90.990 4.000 ;
    END
  END sport1_i[10]
  PIN sport1_i[11]
    DIRECTION INPUT ;
    USE SIGNAL ;
    ANTENNAGATEAREA 0.126000 ;
    PORT
      LAYER met2 ;
        RECT 92.090 0.000 92.370 4.000 ;
    END
  END sport1_i[11]
  PIN sport1_i[12]
    DIRECTION INPUT ;
    USE SIGNAL ;
    ANTENNAGATEAREA 0.126000 ;
    PORT
      LAYER met2 ;
        RECT 93.470 0.000 93.750 4.000 ;
    END
  END sport1_i[12]
  PIN sport1_i[13]
    DIRECTION INPUT ;
    USE SIGNAL ;
    ANTENNAGATEAREA 0.126000 ;
    PORT
      LAYER met2 ;
        RECT 94.850 0.000 95.130 4.000 ;
    END
  END sport1_i[13]
  PIN sport1_i[14]
    DIRECTION INPUT ;
    USE SIGNAL ;
    ANTENNAGATEAREA 0.126000 ;
    PORT
      LAYER met2 ;
        RECT 96.230 0.000 96.510 4.000 ;
    END
  END sport1_i[14]
  PIN sport1_i[15]
    DIRECTION INPUT ;
    USE SIGNAL ;
    ANTENNAGATEAREA 0.126000 ;
    PORT
      LAYER met2 ;
        RECT 97.610 0.000 97.890 4.000 ;
    END
  END sport1_i[15]
  PIN sport1_i[16]
    DIRECTION INPUT ;
    USE SIGNAL ;
    ANTENNAGATEAREA 0.126000 ;
    PORT
      LAYER met2 ;
        RECT 98.990 0.000 99.270 4.000 ;
    END
  END sport1_i[16]
  PIN sport1_i[17]
    DIRECTION INPUT ;
    USE SIGNAL ;
    ANTENNAGATEAREA 0.126000 ;
    PORT
      LAYER met2 ;
        RECT 100.370 0.000 100.650 4.000 ;
    END
  END sport1_i[17]
  PIN sport1_i[18]
    DIRECTION INPUT ;
    USE SIGNAL ;
    ANTENNAGATEAREA 0.196500 ;
    PORT
      LAYER met2 ;
        RECT 101.750 0.000 102.030 4.000 ;
    END
  END sport1_i[18]
  PIN sport1_i[19]
    DIRECTION INPUT ;
    USE SIGNAL ;
    ANTENNAGATEAREA 0.196500 ;
    PORT
      LAYER met2 ;
        RECT 103.130 0.000 103.410 4.000 ;
    END
  END sport1_i[19]
  PIN sport1_i[1]
    DIRECTION INPUT ;
    USE SIGNAL ;
    ANTENNAGATEAREA 0.126000 ;
    PORT
      LAYER met2 ;
        RECT 78.290 0.000 78.570 4.000 ;
    END
  END sport1_i[1]
  PIN sport1_i[20]
    DIRECTION INPUT ;
    USE SIGNAL ;
    ANTENNAGATEAREA 0.126000 ;
    PORT
      LAYER met2 ;
        RECT 104.510 0.000 104.790 4.000 ;
    END
  END sport1_i[20]
  PIN sport1_i[21]
    DIRECTION INPUT ;
    USE SIGNAL ;
    ANTENNAGATEAREA 0.126000 ;
    PORT
      LAYER met2 ;
        RECT 105.890 0.000 106.170 4.000 ;
    END
  END sport1_i[21]
  PIN sport1_i[22]
    DIRECTION INPUT ;
    USE SIGNAL ;
    ANTENNAGATEAREA 0.196500 ;
    PORT
      LAYER met2 ;
        RECT 107.270 0.000 107.550 4.000 ;
    END
  END sport1_i[22]
  PIN sport1_i[23]
    DIRECTION INPUT ;
    USE SIGNAL ;
    ANTENNAGATEAREA 0.196500 ;
    PORT
      LAYER met2 ;
        RECT 108.650 0.000 108.930 4.000 ;
    END
  END sport1_i[23]
  PIN sport1_i[24]
    DIRECTION INPUT ;
    USE SIGNAL ;
    ANTENNAGATEAREA 0.126000 ;
    PORT
      LAYER met2 ;
        RECT 110.030 0.000 110.310 4.000 ;
    END
  END sport1_i[24]
  PIN sport1_i[25]
    DIRECTION INPUT ;
    USE SIGNAL ;
    ANTENNAGATEAREA 0.126000 ;
    PORT
      LAYER met2 ;
        RECT 111.410 0.000 111.690 4.000 ;
    END
  END sport1_i[25]
  PIN sport1_i[26]
    DIRECTION INPUT ;
    USE SIGNAL ;
    ANTENNAGATEAREA 0.126000 ;
    PORT
      LAYER met2 ;
        RECT 112.790 0.000 113.070 4.000 ;
    END
  END sport1_i[26]
  PIN sport1_i[27]
    DIRECTION INPUT ;
    USE SIGNAL ;
    ANTENNAGATEAREA 0.126000 ;
    PORT
      LAYER met2 ;
        RECT 114.170 0.000 114.450 4.000 ;
    END
  END sport1_i[27]
  PIN sport1_i[28]
    DIRECTION INPUT ;
    USE SIGNAL ;
    ANTENNAGATEAREA 0.126000 ;
    PORT
      LAYER met2 ;
        RECT 115.550 0.000 115.830 4.000 ;
    END
  END sport1_i[28]
  PIN sport1_i[29]
    DIRECTION INPUT ;
    USE SIGNAL ;
    ANTENNAGATEAREA 0.126000 ;
    PORT
      LAYER met2 ;
        RECT 116.930 0.000 117.210 4.000 ;
    END
  END sport1_i[29]
  PIN sport1_i[2]
    DIRECTION INPUT ;
    USE SIGNAL ;
    ANTENNAGATEAREA 0.126000 ;
    PORT
      LAYER met2 ;
        RECT 79.670 0.000 79.950 4.000 ;
    END
  END sport1_i[2]
  PIN sport1_i[30]
    DIRECTION INPUT ;
    USE SIGNAL ;
    ANTENNAGATEAREA 0.196500 ;
    PORT
      LAYER met2 ;
        RECT 118.310 0.000 118.590 4.000 ;
    END
  END sport1_i[30]
  PIN sport1_i[31]
    DIRECTION INPUT ;
    USE SIGNAL ;
    ANTENNAGATEAREA 0.196500 ;
    PORT
      LAYER met2 ;
        RECT 119.690 0.000 119.970 4.000 ;
    END
  END sport1_i[31]
  PIN sport1_i[32]
    DIRECTION INPUT ;
    USE SIGNAL ;
    ANTENNAGATEAREA 0.126000 ;
    PORT
      LAYER met2 ;
        RECT 121.070 0.000 121.350 4.000 ;
    END
  END sport1_i[32]
  PIN sport1_i[33]
    DIRECTION INPUT ;
    USE SIGNAL ;
    ANTENNAGATEAREA 0.213000 ;
    PORT
      LAYER met2 ;
        RECT 122.450 0.000 122.730 4.000 ;
    END
  END sport1_i[33]
  PIN sport1_i[34]
    DIRECTION INPUT ;
    USE SIGNAL ;
    ANTENNAGATEAREA 0.126000 ;
    PORT
      LAYER met2 ;
        RECT 123.830 0.000 124.110 4.000 ;
    END
  END sport1_i[34]
  PIN sport1_i[35]
    DIRECTION INPUT ;
    USE SIGNAL ;
    ANTENNAGATEAREA 0.126000 ;
    PORT
      LAYER met2 ;
        RECT 125.210 0.000 125.490 4.000 ;
    END
  END sport1_i[35]
  PIN sport1_i[36]
    DIRECTION INPUT ;
    USE SIGNAL ;
    ANTENNAGATEAREA 0.196500 ;
    PORT
      LAYER met2 ;
        RECT 126.590 0.000 126.870 4.000 ;
    END
  END sport1_i[36]
  PIN sport1_i[37]
    DIRECTION INPUT ;
    USE SIGNAL ;
    ANTENNAGATEAREA 0.213000 ;
    PORT
      LAYER met2 ;
        RECT 127.970 0.000 128.250 4.000 ;
    END
  END sport1_i[37]
  PIN sport1_i[38]
    DIRECTION INPUT ;
    USE SIGNAL ;
    ANTENNAGATEAREA 0.126000 ;
    PORT
      LAYER met2 ;
        RECT 129.350 0.000 129.630 4.000 ;
    END
  END sport1_i[38]
  PIN sport1_i[39]
    DIRECTION INPUT ;
    USE SIGNAL ;
    ANTENNAGATEAREA 0.196500 ;
    PORT
      LAYER met2 ;
        RECT 130.730 0.000 131.010 4.000 ;
    END
  END sport1_i[39]
  PIN sport1_i[3]
    DIRECTION INPUT ;
    USE SIGNAL ;
    ANTENNAGATEAREA 0.126000 ;
    PORT
      LAYER met2 ;
        RECT 81.050 0.000 81.330 4.000 ;
    END
  END sport1_i[3]
  PIN sport1_i[40]
    DIRECTION INPUT ;
    USE SIGNAL ;
    ANTENNAGATEAREA 0.213000 ;
    PORT
      LAYER met2 ;
        RECT 132.110 0.000 132.390 4.000 ;
    END
  END sport1_i[40]
  PIN sport1_i[41]
    DIRECTION INPUT ;
    USE SIGNAL ;
    ANTENNAGATEAREA 0.159000 ;
    PORT
      LAYER met2 ;
        RECT 133.490 0.000 133.770 4.000 ;
    END
  END sport1_i[41]
  PIN sport1_i[42]
    DIRECTION INPUT ;
    USE SIGNAL ;
    ANTENNAGATEAREA 0.159000 ;
    PORT
      LAYER met2 ;
        RECT 134.870 0.000 135.150 4.000 ;
    END
  END sport1_i[42]
  PIN sport1_i[43]
    DIRECTION INPUT ;
    USE SIGNAL ;
    ANTENNAGATEAREA 0.126000 ;
    PORT
      LAYER met2 ;
        RECT 136.250 0.000 136.530 4.000 ;
    END
  END sport1_i[43]
  PIN sport1_i[44]
    DIRECTION INPUT ;
    USE SIGNAL ;
    ANTENNAGATEAREA 0.159000 ;
    PORT
      LAYER met2 ;
        RECT 137.630 0.000 137.910 4.000 ;
    END
  END sport1_i[44]
  PIN sport1_i[45]
    DIRECTION INPUT ;
    USE SIGNAL ;
    ANTENNAGATEAREA 0.213000 ;
    PORT
      LAYER met2 ;
        RECT 139.010 0.000 139.290 4.000 ;
    END
  END sport1_i[45]
  PIN sport1_i[46]
    DIRECTION INPUT ;
    USE SIGNAL ;
    ANTENNAGATEAREA 0.213000 ;
    PORT
      LAYER met2 ;
        RECT 140.390 0.000 140.670 4.000 ;
    END
  END sport1_i[46]
  PIN sport1_i[47]
    DIRECTION INPUT ;
    USE SIGNAL ;
    ANTENNAGATEAREA 0.213000 ;
    PORT
      LAYER met2 ;
        RECT 141.770 0.000 142.050 4.000 ;
    END
  END sport1_i[47]
  PIN sport1_i[48]
    DIRECTION INPUT ;
    USE SIGNAL ;
    ANTENNAGATEAREA 0.213000 ;
    PORT
      LAYER met2 ;
        RECT 143.150 0.000 143.430 4.000 ;
    END
  END sport1_i[48]
  PIN sport1_i[49]
    DIRECTION INPUT ;
    USE SIGNAL ;
    ANTENNAGATEAREA 0.159000 ;
    PORT
      LAYER met2 ;
        RECT 144.530 0.000 144.810 4.000 ;
    END
  END sport1_i[49]
  PIN sport1_i[4]
    DIRECTION INPUT ;
    USE SIGNAL ;
    ANTENNAGATEAREA 0.213000 ;
    PORT
      LAYER met2 ;
        RECT 82.430 0.000 82.710 4.000 ;
    END
  END sport1_i[4]
  PIN sport1_i[50]
    DIRECTION INPUT ;
    USE SIGNAL ;
    ANTENNAGATEAREA 0.213000 ;
    PORT
      LAYER met2 ;
        RECT 145.910 0.000 146.190 4.000 ;
    END
  END sport1_i[50]
  PIN sport1_i[51]
    DIRECTION INPUT ;
    USE SIGNAL ;
    ANTENNAGATEAREA 0.213000 ;
    PORT
      LAYER met2 ;
        RECT 147.290 0.000 147.570 4.000 ;
    END
  END sport1_i[51]
  PIN sport1_i[52]
    DIRECTION INPUT ;
    USE SIGNAL ;
    ANTENNAGATEAREA 0.213000 ;
    PORT
      LAYER met2 ;
        RECT 148.670 0.000 148.950 4.000 ;
    END
  END sport1_i[52]
  PIN sport1_i[53]
    DIRECTION INPUT ;
    USE SIGNAL ;
    ANTENNAGATEAREA 0.213000 ;
    PORT
      LAYER met2 ;
        RECT 150.050 0.000 150.330 4.000 ;
    END
  END sport1_i[53]
  PIN sport1_i[54]
    DIRECTION INPUT ;
    USE SIGNAL ;
    ANTENNAGATEAREA 0.196500 ;
    PORT
      LAYER met2 ;
        RECT 151.430 0.000 151.710 4.000 ;
    END
  END sport1_i[54]
  PIN sport1_i[55]
    DIRECTION INPUT ;
    USE SIGNAL ;
    ANTENNAGATEAREA 0.196500 ;
    PORT
      LAYER met2 ;
        RECT 152.810 0.000 153.090 4.000 ;
    END
  END sport1_i[55]
  PIN sport1_i[56]
    DIRECTION INPUT ;
    USE SIGNAL ;
    ANTENNAGATEAREA 0.196500 ;
    PORT
      LAYER met2 ;
        RECT 154.190 0.000 154.470 4.000 ;
    END
  END sport1_i[56]
  PIN sport1_i[57]
    DIRECTION INPUT ;
    USE SIGNAL ;
    ANTENNAGATEAREA 0.196500 ;
    PORT
      LAYER met2 ;
        RECT 155.570 0.000 155.850 4.000 ;
    END
  END sport1_i[57]
  PIN sport1_i[58]
    DIRECTION INPUT ;
    USE SIGNAL ;
    ANTENNAGATEAREA 0.196500 ;
    PORT
      LAYER met2 ;
        RECT 156.950 0.000 157.230 4.000 ;
    END
  END sport1_i[58]
  PIN sport1_i[59]
    DIRECTION INPUT ;
    USE SIGNAL ;
    ANTENNAGATEAREA 0.196500 ;
    PORT
      LAYER met2 ;
        RECT 158.330 0.000 158.610 4.000 ;
    END
  END sport1_i[59]
  PIN sport1_i[5]
    DIRECTION INPUT ;
    USE SIGNAL ;
    ANTENNAGATEAREA 0.213000 ;
    PORT
      LAYER met2 ;
        RECT 83.810 0.000 84.090 4.000 ;
    END
  END sport1_i[5]
  PIN sport1_i[60]
    DIRECTION INPUT ;
    USE SIGNAL ;
    ANTENNAGATEAREA 0.196500 ;
    PORT
      LAYER met2 ;
        RECT 159.710 0.000 159.990 4.000 ;
    END
  END sport1_i[60]
  PIN sport1_i[61]
    DIRECTION INPUT ;
    USE SIGNAL ;
    ANTENNAGATEAREA 0.196500 ;
    PORT
      LAYER met2 ;
        RECT 161.090 0.000 161.370 4.000 ;
    END
  END sport1_i[61]
  PIN sport1_i[62]
    DIRECTION INPUT ;
    USE SIGNAL ;
    ANTENNAGATEAREA 0.196500 ;
    PORT
      LAYER met2 ;
        RECT 162.470 0.000 162.750 4.000 ;
    END
  END sport1_i[62]
  PIN sport1_i[63]
    DIRECTION INPUT ;
    USE SIGNAL ;
    ANTENNAGATEAREA 0.196500 ;
    PORT
      LAYER met2 ;
        RECT 163.850 0.000 164.130 4.000 ;
    END
  END sport1_i[63]
  PIN sport1_i[64]
    DIRECTION INPUT ;
    USE SIGNAL ;
    ANTENNAGATEAREA 0.159000 ;
    PORT
      LAYER met2 ;
        RECT 165.230 0.000 165.510 4.000 ;
    END
  END sport1_i[64]
  PIN sport1_i[65]
    DIRECTION INPUT ;
    USE SIGNAL ;
    ANTENNAGATEAREA 0.213000 ;
    PORT
      LAYER met2 ;
        RECT 166.610 0.000 166.890 4.000 ;
    END
  END sport1_i[65]
  PIN sport1_i[66]
    DIRECTION INPUT ;
    USE SIGNAL ;
    ANTENNAGATEAREA 0.213000 ;
    PORT
      LAYER met2 ;
        RECT 167.990 0.000 168.270 4.000 ;
    END
  END sport1_i[66]
  PIN sport1_i[67]
    DIRECTION INPUT ;
    USE SIGNAL ;
    ANTENNAGATEAREA 0.159000 ;
    PORT
      LAYER met2 ;
        RECT 169.370 0.000 169.650 4.000 ;
    END
  END sport1_i[67]
  PIN sport1_i[68]
    DIRECTION INPUT ;
    USE SIGNAL ;
    ANTENNAGATEAREA 0.159000 ;
    PORT
      LAYER met2 ;
        RECT 170.750 0.000 171.030 4.000 ;
    END
  END sport1_i[68]
  PIN sport1_i[6]
    DIRECTION INPUT ;
    USE SIGNAL ;
    ANTENNAGATEAREA 0.213000 ;
    PORT
      LAYER met2 ;
        RECT 85.190 0.000 85.470 4.000 ;
    END
  END sport1_i[6]
  PIN sport1_i[7]
    DIRECTION INPUT ;
    USE SIGNAL ;
    ANTENNAGATEAREA 0.213000 ;
    PORT
      LAYER met2 ;
        RECT 86.570 0.000 86.850 4.000 ;
    END
  END sport1_i[7]
  PIN sport1_i[8]
    DIRECTION INPUT ;
    USE SIGNAL ;
    ANTENNAGATEAREA 0.126000 ;
    PORT
      LAYER met2 ;
        RECT 87.950 0.000 88.230 4.000 ;
    END
  END sport1_i[8]
  PIN sport1_i[9]
    DIRECTION INPUT ;
    USE SIGNAL ;
    ANTENNAGATEAREA 0.126000 ;
    PORT
      LAYER met2 ;
        RECT 89.330 0.000 89.610 4.000 ;
    END
  END sport1_i[9]
  PIN sport1_o[0]
    DIRECTION OUTPUT TRISTATE ;
    USE SIGNAL ;
    ANTENNADIFFAREA 0.795200 ;
    PORT
      LAYER met2 ;
        RECT 29.990 0.000 30.270 4.000 ;
    END
  END sport1_o[0]
  PIN sport1_o[10]
    DIRECTION OUTPUT TRISTATE ;
    USE SIGNAL ;
    ANTENNADIFFAREA 0.795200 ;
    PORT
      LAYER met2 ;
        RECT 43.790 0.000 44.070 4.000 ;
    END
  END sport1_o[10]
  PIN sport1_o[11]
    DIRECTION OUTPUT TRISTATE ;
    USE SIGNAL ;
    ANTENNADIFFAREA 0.795200 ;
    PORT
      LAYER met2 ;
        RECT 45.170 0.000 45.450 4.000 ;
    END
  END sport1_o[11]
  PIN sport1_o[12]
    DIRECTION OUTPUT TRISTATE ;
    USE SIGNAL ;
    ANTENNADIFFAREA 0.795200 ;
    PORT
      LAYER met2 ;
        RECT 46.550 0.000 46.830 4.000 ;
    END
  END sport1_o[12]
  PIN sport1_o[13]
    DIRECTION OUTPUT TRISTATE ;
    USE SIGNAL ;
    ANTENNADIFFAREA 0.795200 ;
    PORT
      LAYER met2 ;
        RECT 47.930 0.000 48.210 4.000 ;
    END
  END sport1_o[13]
  PIN sport1_o[14]
    DIRECTION OUTPUT TRISTATE ;
    USE SIGNAL ;
    ANTENNADIFFAREA 0.795200 ;
    PORT
      LAYER met2 ;
        RECT 49.310 0.000 49.590 4.000 ;
    END
  END sport1_o[14]
  PIN sport1_o[15]
    DIRECTION OUTPUT TRISTATE ;
    USE SIGNAL ;
    ANTENNADIFFAREA 0.795200 ;
    PORT
      LAYER met2 ;
        RECT 50.690 0.000 50.970 4.000 ;
    END
  END sport1_o[15]
  PIN sport1_o[16]
    DIRECTION OUTPUT TRISTATE ;
    USE SIGNAL ;
    ANTENNADIFFAREA 0.795200 ;
    PORT
      LAYER met2 ;
        RECT 52.070 0.000 52.350 4.000 ;
    END
  END sport1_o[16]
  PIN sport1_o[17]
    DIRECTION OUTPUT TRISTATE ;
    USE SIGNAL ;
    ANTENNADIFFAREA 0.795200 ;
    PORT
      LAYER met2 ;
        RECT 53.450 0.000 53.730 4.000 ;
    END
  END sport1_o[17]
  PIN sport1_o[18]
    DIRECTION OUTPUT TRISTATE ;
    USE SIGNAL ;
    ANTENNADIFFAREA 0.795200 ;
    PORT
      LAYER met2 ;
        RECT 54.830 0.000 55.110 4.000 ;
    END
  END sport1_o[18]
  PIN sport1_o[19]
    DIRECTION OUTPUT TRISTATE ;
    USE SIGNAL ;
    ANTENNADIFFAREA 0.795200 ;
    PORT
      LAYER met2 ;
        RECT 56.210 0.000 56.490 4.000 ;
    END
  END sport1_o[19]
  PIN sport1_o[1]
    DIRECTION OUTPUT TRISTATE ;
    USE SIGNAL ;
    ANTENNADIFFAREA 0.795200 ;
    PORT
      LAYER met2 ;
        RECT 31.370 0.000 31.650 4.000 ;
    END
  END sport1_o[1]
  PIN sport1_o[20]
    DIRECTION OUTPUT TRISTATE ;
    USE SIGNAL ;
    ANTENNADIFFAREA 0.795200 ;
    PORT
      LAYER met2 ;
        RECT 57.590 0.000 57.870 4.000 ;
    END
  END sport1_o[20]
  PIN sport1_o[21]
    DIRECTION OUTPUT TRISTATE ;
    USE SIGNAL ;
    ANTENNADIFFAREA 0.795200 ;
    PORT
      LAYER met2 ;
        RECT 58.970 0.000 59.250 4.000 ;
    END
  END sport1_o[21]
  PIN sport1_o[22]
    DIRECTION OUTPUT TRISTATE ;
    USE SIGNAL ;
    ANTENNADIFFAREA 0.795200 ;
    PORT
      LAYER met2 ;
        RECT 60.350 0.000 60.630 4.000 ;
    END
  END sport1_o[22]
  PIN sport1_o[23]
    DIRECTION OUTPUT TRISTATE ;
    USE SIGNAL ;
    ANTENNADIFFAREA 0.795200 ;
    PORT
      LAYER met2 ;
        RECT 61.730 0.000 62.010 4.000 ;
    END
  END sport1_o[23]
  PIN sport1_o[24]
    DIRECTION OUTPUT TRISTATE ;
    USE SIGNAL ;
    ANTENNADIFFAREA 0.795200 ;
    PORT
      LAYER met2 ;
        RECT 63.110 0.000 63.390 4.000 ;
    END
  END sport1_o[24]
  PIN sport1_o[25]
    DIRECTION OUTPUT TRISTATE ;
    USE SIGNAL ;
    ANTENNADIFFAREA 0.795200 ;
    PORT
      LAYER met2 ;
        RECT 64.490 0.000 64.770 4.000 ;
    END
  END sport1_o[25]
  PIN sport1_o[26]
    DIRECTION OUTPUT TRISTATE ;
    USE SIGNAL ;
    ANTENNADIFFAREA 0.795200 ;
    PORT
      LAYER met2 ;
        RECT 65.870 0.000 66.150 4.000 ;
    END
  END sport1_o[26]
  PIN sport1_o[27]
    DIRECTION OUTPUT TRISTATE ;
    USE SIGNAL ;
    ANTENNADIFFAREA 0.795200 ;
    PORT
      LAYER met2 ;
        RECT 67.250 0.000 67.530 4.000 ;
    END
  END sport1_o[27]
  PIN sport1_o[28]
    DIRECTION OUTPUT TRISTATE ;
    USE SIGNAL ;
    ANTENNADIFFAREA 0.795200 ;
    PORT
      LAYER met2 ;
        RECT 68.630 0.000 68.910 4.000 ;
    END
  END sport1_o[28]
  PIN sport1_o[29]
    DIRECTION OUTPUT TRISTATE ;
    USE SIGNAL ;
    ANTENNADIFFAREA 0.795200 ;
    PORT
      LAYER met2 ;
        RECT 70.010 0.000 70.290 4.000 ;
    END
  END sport1_o[29]
  PIN sport1_o[2]
    DIRECTION OUTPUT TRISTATE ;
    USE SIGNAL ;
    ANTENNADIFFAREA 0.795200 ;
    PORT
      LAYER met2 ;
        RECT 32.750 0.000 33.030 4.000 ;
    END
  END sport1_o[2]
  PIN sport1_o[30]
    DIRECTION OUTPUT TRISTATE ;
    USE SIGNAL ;
    ANTENNADIFFAREA 0.795200 ;
    PORT
      LAYER met2 ;
        RECT 71.390 0.000 71.670 4.000 ;
    END
  END sport1_o[30]
  PIN sport1_o[31]
    DIRECTION OUTPUT TRISTATE ;
    USE SIGNAL ;
    ANTENNADIFFAREA 0.795200 ;
    PORT
      LAYER met2 ;
        RECT 72.770 0.000 73.050 4.000 ;
    END
  END sport1_o[31]
  PIN sport1_o[32]
    DIRECTION OUTPUT TRISTATE ;
    USE SIGNAL ;
    ANTENNADIFFAREA 0.795200 ;
    PORT
      LAYER met2 ;
        RECT 74.150 0.000 74.430 4.000 ;
    END
  END sport1_o[32]
  PIN sport1_o[33]
    DIRECTION OUTPUT TRISTATE ;
    USE SIGNAL ;
    ANTENNADIFFAREA 0.795200 ;
    PORT
      LAYER met2 ;
        RECT 75.530 0.000 75.810 4.000 ;
    END
  END sport1_o[33]
  PIN sport1_o[3]
    DIRECTION OUTPUT TRISTATE ;
    USE SIGNAL ;
    ANTENNADIFFAREA 0.795200 ;
    PORT
      LAYER met2 ;
        RECT 34.130 0.000 34.410 4.000 ;
    END
  END sport1_o[3]
  PIN sport1_o[4]
    DIRECTION OUTPUT TRISTATE ;
    USE SIGNAL ;
    ANTENNADIFFAREA 0.795200 ;
    PORT
      LAYER met2 ;
        RECT 35.510 0.000 35.790 4.000 ;
    END
  END sport1_o[4]
  PIN sport1_o[5]
    DIRECTION OUTPUT TRISTATE ;
    USE SIGNAL ;
    ANTENNADIFFAREA 0.795200 ;
    PORT
      LAYER met2 ;
        RECT 36.890 0.000 37.170 4.000 ;
    END
  END sport1_o[5]
  PIN sport1_o[6]
    DIRECTION OUTPUT TRISTATE ;
    USE SIGNAL ;
    ANTENNADIFFAREA 0.795200 ;
    PORT
      LAYER met2 ;
        RECT 38.270 0.000 38.550 4.000 ;
    END
  END sport1_o[6]
  PIN sport1_o[7]
    DIRECTION OUTPUT TRISTATE ;
    USE SIGNAL ;
    ANTENNADIFFAREA 0.795200 ;
    PORT
      LAYER met2 ;
        RECT 39.650 0.000 39.930 4.000 ;
    END
  END sport1_o[7]
  PIN sport1_o[8]
    DIRECTION OUTPUT TRISTATE ;
    USE SIGNAL ;
    ANTENNADIFFAREA 0.795200 ;
    PORT
      LAYER met2 ;
        RECT 41.030 0.000 41.310 4.000 ;
    END
  END sport1_o[8]
  PIN sport1_o[9]
    DIRECTION OUTPUT TRISTATE ;
    USE SIGNAL ;
    ANTENNADIFFAREA 0.795200 ;
    PORT
      LAYER met2 ;
        RECT 42.410 0.000 42.690 4.000 ;
    END
  END sport1_o[9]
  PIN sport2_i[0]
    DIRECTION INPUT ;
    USE SIGNAL ;
    ANTENNAGATEAREA 0.196500 ;
    PORT
      LAYER met2 ;
        RECT 77.370 0.000 77.650 4.000 ;
    END
  END sport2_i[0]
  PIN sport2_i[10]
    DIRECTION INPUT ;
    USE SIGNAL ;
    ANTENNAGATEAREA 0.196500 ;
    PORT
      LAYER met2 ;
        RECT 91.170 0.000 91.450 4.000 ;
    END
  END sport2_i[10]
  PIN sport2_i[11]
    DIRECTION INPUT ;
    USE SIGNAL ;
    ANTENNAGATEAREA 0.196500 ;
    PORT
      LAYER met2 ;
        RECT 92.550 0.000 92.830 4.000 ;
    END
  END sport2_i[11]
  PIN sport2_i[12]
    DIRECTION INPUT ;
    USE SIGNAL ;
    ANTENNAGATEAREA 0.196500 ;
    PORT
      LAYER met2 ;
        RECT 93.930 0.000 94.210 4.000 ;
    END
  END sport2_i[12]
  PIN sport2_i[13]
    DIRECTION INPUT ;
    USE SIGNAL ;
    ANTENNAGATEAREA 0.196500 ;
    PORT
      LAYER met2 ;
        RECT 95.310 0.000 95.590 4.000 ;
    END
  END sport2_i[13]
  PIN sport2_i[14]
    DIRECTION INPUT ;
    USE SIGNAL ;
    ANTENNAGATEAREA 0.196500 ;
    PORT
      LAYER met2 ;
        RECT 96.690 0.000 96.970 4.000 ;
    END
  END sport2_i[14]
  PIN sport2_i[15]
    DIRECTION INPUT ;
    USE SIGNAL ;
    ANTENNAGATEAREA 0.196500 ;
    PORT
      LAYER met2 ;
        RECT 98.070 0.000 98.350 4.000 ;
    END
  END sport2_i[15]
  PIN sport2_i[16]
    DIRECTION INPUT ;
    USE SIGNAL ;
    ANTENNAGATEAREA 0.196500 ;
    PORT
      LAYER met2 ;
        RECT 99.450 0.000 99.730 4.000 ;
    END
  END sport2_i[16]
  PIN sport2_i[17]
    DIRECTION INPUT ;
    USE SIGNAL ;
    ANTENNAGATEAREA 0.196500 ;
    ANTENNADIFFAREA 0.434700 ;
    PORT
      LAYER met2 ;
        RECT 100.830 0.000 101.110 4.000 ;
    END
  END sport2_i[17]
  PIN sport2_i[18]
    DIRECTION INPUT ;
    USE SIGNAL ;
    ANTENNAGATEAREA 0.196500 ;
    PORT
      LAYER met2 ;
        RECT 102.210 0.000 102.490 4.000 ;
    END
  END sport2_i[18]
  PIN sport2_i[19]
    DIRECTION INPUT ;
    USE SIGNAL ;
    ANTENNAGATEAREA 0.196500 ;
    PORT
      LAYER met2 ;
        RECT 103.590 0.000 103.870 4.000 ;
    END
  END sport2_i[19]
  PIN sport2_i[1]
    DIRECTION INPUT ;
    USE SIGNAL ;
    ANTENNAGATEAREA 0.196500 ;
    PORT
      LAYER met2 ;
        RECT 78.750 0.000 79.030 4.000 ;
    END
  END sport2_i[1]
  PIN sport2_i[20]
    DIRECTION INPUT ;
    USE SIGNAL ;
    ANTENNAGATEAREA 0.196500 ;
    PORT
      LAYER met2 ;
        RECT 104.970 0.000 105.250 4.000 ;
    END
  END sport2_i[20]
  PIN sport2_i[21]
    DIRECTION INPUT ;
    USE SIGNAL ;
    ANTENNAGATEAREA 0.196500 ;
    PORT
      LAYER met2 ;
        RECT 106.350 0.000 106.630 4.000 ;
    END
  END sport2_i[21]
  PIN sport2_i[22]
    DIRECTION INPUT ;
    USE SIGNAL ;
    ANTENNAGATEAREA 0.196500 ;
    PORT
      LAYER met2 ;
        RECT 107.730 0.000 108.010 4.000 ;
    END
  END sport2_i[22]
  PIN sport2_i[23]
    DIRECTION INPUT ;
    USE SIGNAL ;
    ANTENNAGATEAREA 0.196500 ;
    PORT
      LAYER met2 ;
        RECT 109.110 0.000 109.390 4.000 ;
    END
  END sport2_i[23]
  PIN sport2_i[24]
    DIRECTION INPUT ;
    USE SIGNAL ;
    ANTENNAGATEAREA 0.196500 ;
    PORT
      LAYER met2 ;
        RECT 110.490 0.000 110.770 4.000 ;
    END
  END sport2_i[24]
  PIN sport2_i[25]
    DIRECTION INPUT ;
    USE SIGNAL ;
    ANTENNAGATEAREA 0.196500 ;
    PORT
      LAYER met2 ;
        RECT 111.870 0.000 112.150 4.000 ;
    END
  END sport2_i[25]
  PIN sport2_i[26]
    DIRECTION INPUT ;
    USE SIGNAL ;
    ANTENNAGATEAREA 0.196500 ;
    PORT
      LAYER met2 ;
        RECT 113.250 0.000 113.530 4.000 ;
    END
  END sport2_i[26]
  PIN sport2_i[27]
    DIRECTION INPUT ;
    USE SIGNAL ;
    ANTENNAGATEAREA 0.196500 ;
    PORT
      LAYER met2 ;
        RECT 114.630 0.000 114.910 4.000 ;
    END
  END sport2_i[27]
  PIN sport2_i[28]
    DIRECTION INPUT ;
    USE SIGNAL ;
    ANTENNAGATEAREA 0.196500 ;
    PORT
      LAYER met2 ;
        RECT 116.010 0.000 116.290 4.000 ;
    END
  END sport2_i[28]
  PIN sport2_i[29]
    DIRECTION INPUT ;
    USE SIGNAL ;
    ANTENNAGATEAREA 0.196500 ;
    PORT
      LAYER met2 ;
        RECT 117.390 0.000 117.670 4.000 ;
    END
  END sport2_i[29]
  PIN sport2_i[2]
    DIRECTION INPUT ;
    USE SIGNAL ;
    ANTENNAGATEAREA 0.196500 ;
    PORT
      LAYER met2 ;
        RECT 80.130 0.000 80.410 4.000 ;
    END
  END sport2_i[2]
  PIN sport2_i[30]
    DIRECTION INPUT ;
    USE SIGNAL ;
    ANTENNAGATEAREA 0.196500 ;
    PORT
      LAYER met2 ;
        RECT 118.770 0.000 119.050 4.000 ;
    END
  END sport2_i[30]
  PIN sport2_i[31]
    DIRECTION INPUT ;
    USE SIGNAL ;
    ANTENNAGATEAREA 0.196500 ;
    PORT
      LAYER met2 ;
        RECT 120.150 0.000 120.430 4.000 ;
    END
  END sport2_i[31]
  PIN sport2_i[32]
    DIRECTION INPUT ;
    USE SIGNAL ;
    ANTENNAGATEAREA 0.196500 ;
    PORT
      LAYER met2 ;
        RECT 121.530 0.000 121.810 4.000 ;
    END
  END sport2_i[32]
  PIN sport2_i[33]
    DIRECTION INPUT ;
    USE SIGNAL ;
    ANTENNAGATEAREA 0.196500 ;
    PORT
      LAYER met2 ;
        RECT 122.910 0.000 123.190 4.000 ;
    END
  END sport2_i[33]
  PIN sport2_i[34]
    DIRECTION INPUT ;
    USE SIGNAL ;
    ANTENNAGATEAREA 0.196500 ;
    PORT
      LAYER met2 ;
        RECT 124.290 0.000 124.570 4.000 ;
    END
  END sport2_i[34]
  PIN sport2_i[35]
    DIRECTION INPUT ;
    USE SIGNAL ;
    ANTENNAGATEAREA 0.196500 ;
    PORT
      LAYER met2 ;
        RECT 125.670 0.000 125.950 4.000 ;
    END
  END sport2_i[35]
  PIN sport2_i[36]
    DIRECTION INPUT ;
    USE SIGNAL ;
    ANTENNAGATEAREA 0.196500 ;
    PORT
      LAYER met2 ;
        RECT 127.050 0.000 127.330 4.000 ;
    END
  END sport2_i[36]
  PIN sport2_i[37]
    DIRECTION INPUT ;
    USE SIGNAL ;
    ANTENNAGATEAREA 0.196500 ;
    PORT
      LAYER met2 ;
        RECT 128.430 0.000 128.710 4.000 ;
    END
  END sport2_i[37]
  PIN sport2_i[38]
    DIRECTION INPUT ;
    USE SIGNAL ;
    ANTENNAGATEAREA 0.196500 ;
    PORT
      LAYER met2 ;
        RECT 129.810 0.000 130.090 4.000 ;
    END
  END sport2_i[38]
  PIN sport2_i[39]
    DIRECTION INPUT ;
    USE SIGNAL ;
    ANTENNAGATEAREA 0.196500 ;
    PORT
      LAYER met2 ;
        RECT 131.190 0.000 131.470 4.000 ;
    END
  END sport2_i[39]
  PIN sport2_i[3]
    DIRECTION INPUT ;
    USE SIGNAL ;
    ANTENNAGATEAREA 0.196500 ;
    PORT
      LAYER met2 ;
        RECT 81.510 0.000 81.790 4.000 ;
    END
  END sport2_i[3]
  PIN sport2_i[40]
    DIRECTION INPUT ;
    USE SIGNAL ;
    ANTENNAGATEAREA 0.196500 ;
    PORT
      LAYER met2 ;
        RECT 132.570 0.000 132.850 4.000 ;
    END
  END sport2_i[40]
  PIN sport2_i[41]
    DIRECTION INPUT ;
    USE SIGNAL ;
    ANTENNAGATEAREA 0.159000 ;
    PORT
      LAYER met2 ;
        RECT 133.950 0.000 134.230 4.000 ;
    END
  END sport2_i[41]
  PIN sport2_i[42]
    DIRECTION INPUT ;
    USE SIGNAL ;
    ANTENNAGATEAREA 0.213000 ;
    PORT
      LAYER met2 ;
        RECT 135.330 0.000 135.610 4.000 ;
    END
  END sport2_i[42]
  PIN sport2_i[43]
    DIRECTION INPUT ;
    USE SIGNAL ;
    ANTENNAGATEAREA 0.213000 ;
    PORT
      LAYER met2 ;
        RECT 136.710 0.000 136.990 4.000 ;
    END
  END sport2_i[43]
  PIN sport2_i[44]
    DIRECTION INPUT ;
    USE SIGNAL ;
    ANTENNAGATEAREA 0.196500 ;
    PORT
      LAYER met2 ;
        RECT 138.090 0.000 138.370 4.000 ;
    END
  END sport2_i[44]
  PIN sport2_i[45]
    DIRECTION INPUT ;
    USE SIGNAL ;
    ANTENNAGATEAREA 0.126000 ;
    PORT
      LAYER met2 ;
        RECT 139.470 0.000 139.750 4.000 ;
    END
  END sport2_i[45]
  PIN sport2_i[46]
    DIRECTION INPUT ;
    USE SIGNAL ;
    ANTENNAGATEAREA 0.196500 ;
    PORT
      LAYER met2 ;
        RECT 140.850 0.000 141.130 4.000 ;
    END
  END sport2_i[46]
  PIN sport2_i[47]
    DIRECTION INPUT ;
    USE SIGNAL ;
    ANTENNAGATEAREA 0.196500 ;
    PORT
      LAYER met2 ;
        RECT 142.230 0.000 142.510 4.000 ;
    END
  END sport2_i[47]
  PIN sport2_i[48]
    DIRECTION INPUT ;
    USE SIGNAL ;
    ANTENNAGATEAREA 0.126000 ;
    PORT
      LAYER met2 ;
        RECT 143.610 0.000 143.890 4.000 ;
    END
  END sport2_i[48]
  PIN sport2_i[49]
    DIRECTION INPUT ;
    USE SIGNAL ;
    ANTENNAGATEAREA 0.196500 ;
    PORT
      LAYER met2 ;
        RECT 144.990 0.000 145.270 4.000 ;
    END
  END sport2_i[49]
  PIN sport2_i[4]
    DIRECTION INPUT ;
    USE SIGNAL ;
    ANTENNAGATEAREA 0.213000 ;
    PORT
      LAYER met2 ;
        RECT 82.890 0.000 83.170 4.000 ;
    END
  END sport2_i[4]
  PIN sport2_i[50]
    DIRECTION INPUT ;
    USE SIGNAL ;
    ANTENNAGATEAREA 0.213000 ;
    PORT
      LAYER met2 ;
        RECT 146.370 0.000 146.650 4.000 ;
    END
  END sport2_i[50]
  PIN sport2_i[51]
    DIRECTION INPUT ;
    USE SIGNAL ;
    ANTENNAGATEAREA 0.213000 ;
    PORT
      LAYER met2 ;
        RECT 147.750 0.000 148.030 4.000 ;
    END
  END sport2_i[51]
  PIN sport2_i[52]
    DIRECTION INPUT ;
    USE SIGNAL ;
    ANTENNAGATEAREA 0.196500 ;
    PORT
      LAYER met2 ;
        RECT 149.130 0.000 149.410 4.000 ;
    END
  END sport2_i[52]
  PIN sport2_i[53]
    DIRECTION INPUT ;
    USE SIGNAL ;
    ANTENNAGATEAREA 0.196500 ;
    PORT
      LAYER met2 ;
        RECT 150.510 0.000 150.790 4.000 ;
    END
  END sport2_i[53]
  PIN sport2_i[54]
    DIRECTION INPUT ;
    USE SIGNAL ;
    ANTENNAGATEAREA 0.196500 ;
    PORT
      LAYER met2 ;
        RECT 151.890 0.000 152.170 4.000 ;
    END
  END sport2_i[54]
  PIN sport2_i[55]
    DIRECTION INPUT ;
    USE SIGNAL ;
    ANTENNAGATEAREA 0.196500 ;
    PORT
      LAYER met2 ;
        RECT 153.270 0.000 153.550 4.000 ;
    END
  END sport2_i[55]
  PIN sport2_i[56]
    DIRECTION INPUT ;
    USE SIGNAL ;
    ANTENNAGATEAREA 0.196500 ;
    PORT
      LAYER met2 ;
        RECT 154.650 0.000 154.930 4.000 ;
    END
  END sport2_i[56]
  PIN sport2_i[57]
    DIRECTION INPUT ;
    USE SIGNAL ;
    ANTENNAGATEAREA 0.196500 ;
    PORT
      LAYER met2 ;
        RECT 156.030 0.000 156.310 4.000 ;
    END
  END sport2_i[57]
  PIN sport2_i[58]
    DIRECTION INPUT ;
    USE SIGNAL ;
    ANTENNAGATEAREA 0.196500 ;
    PORT
      LAYER met2 ;
        RECT 157.410 0.000 157.690 4.000 ;
    END
  END sport2_i[58]
  PIN sport2_i[59]
    DIRECTION INPUT ;
    USE SIGNAL ;
    ANTENNAGATEAREA 0.196500 ;
    PORT
      LAYER met2 ;
        RECT 158.790 0.000 159.070 4.000 ;
    END
  END sport2_i[59]
  PIN sport2_i[5]
    DIRECTION INPUT ;
    USE SIGNAL ;
    ANTENNAGATEAREA 0.213000 ;
    PORT
      LAYER met2 ;
        RECT 84.270 0.000 84.550 4.000 ;
    END
  END sport2_i[5]
  PIN sport2_i[60]
    DIRECTION INPUT ;
    USE SIGNAL ;
    ANTENNAGATEAREA 0.196500 ;
    PORT
      LAYER met2 ;
        RECT 160.170 0.000 160.450 4.000 ;
    END
  END sport2_i[60]
  PIN sport2_i[61]
    DIRECTION INPUT ;
    USE SIGNAL ;
    ANTENNAGATEAREA 0.196500 ;
    PORT
      LAYER met2 ;
        RECT 161.550 0.000 161.830 4.000 ;
    END
  END sport2_i[61]
  PIN sport2_i[62]
    DIRECTION INPUT ;
    USE SIGNAL ;
    ANTENNAGATEAREA 0.196500 ;
    PORT
      LAYER met2 ;
        RECT 162.930 0.000 163.210 4.000 ;
    END
  END sport2_i[62]
  PIN sport2_i[63]
    DIRECTION INPUT ;
    USE SIGNAL ;
    ANTENNAGATEAREA 0.196500 ;
    PORT
      LAYER met2 ;
        RECT 164.310 0.000 164.590 4.000 ;
    END
  END sport2_i[63]
  PIN sport2_i[64]
    DIRECTION INPUT ;
    USE SIGNAL ;
    ANTENNAGATEAREA 0.213000 ;
    PORT
      LAYER met2 ;
        RECT 165.690 0.000 165.970 4.000 ;
    END
  END sport2_i[64]
  PIN sport2_i[65]
    DIRECTION INPUT ;
    USE SIGNAL ;
    ANTENNAGATEAREA 0.196500 ;
    PORT
      LAYER met2 ;
        RECT 167.070 0.000 167.350 4.000 ;
    END
  END sport2_i[65]
  PIN sport2_i[66]
    DIRECTION INPUT ;
    USE SIGNAL ;
    ANTENNAGATEAREA 0.196500 ;
    PORT
      LAYER met2 ;
        RECT 168.450 0.000 168.730 4.000 ;
    END
  END sport2_i[66]
  PIN sport2_i[67]
    DIRECTION INPUT ;
    USE SIGNAL ;
    ANTENNAGATEAREA 0.196500 ;
    PORT
      LAYER met2 ;
        RECT 169.830 0.000 170.110 4.000 ;
    END
  END sport2_i[67]
  PIN sport2_i[68]
    DIRECTION INPUT ;
    USE SIGNAL ;
    ANTENNAGATEAREA 0.213000 ;
    PORT
      LAYER met2 ;
        RECT 171.210 0.000 171.490 4.000 ;
    END
  END sport2_i[68]
  PIN sport2_i[6]
    DIRECTION INPUT ;
    USE SIGNAL ;
    ANTENNAGATEAREA 0.213000 ;
    PORT
      LAYER met2 ;
        RECT 85.650 0.000 85.930 4.000 ;
    END
  END sport2_i[6]
  PIN sport2_i[7]
    DIRECTION INPUT ;
    USE SIGNAL ;
    ANTENNAGATEAREA 0.213000 ;
    PORT
      LAYER met2 ;
        RECT 87.030 0.000 87.310 4.000 ;
    END
  END sport2_i[7]
  PIN sport2_i[8]
    DIRECTION INPUT ;
    USE SIGNAL ;
    ANTENNAGATEAREA 0.196500 ;
    PORT
      LAYER met2 ;
        RECT 88.410 0.000 88.690 4.000 ;
    END
  END sport2_i[8]
  PIN sport2_i[9]
    DIRECTION INPUT ;
    USE SIGNAL ;
    ANTENNAGATEAREA 0.196500 ;
    PORT
      LAYER met2 ;
        RECT 89.790 0.000 90.070 4.000 ;
    END
  END sport2_i[9]
  PIN sport2_o[0]
    DIRECTION OUTPUT TRISTATE ;
    USE SIGNAL ;
    ANTENNADIFFAREA 0.795200 ;
    PORT
      LAYER met2 ;
        RECT 30.450 0.000 30.730 4.000 ;
    END
  END sport2_o[0]
  PIN sport2_o[10]
    DIRECTION OUTPUT TRISTATE ;
    USE SIGNAL ;
    ANTENNADIFFAREA 0.795200 ;
    PORT
      LAYER met2 ;
        RECT 44.250 0.000 44.530 4.000 ;
    END
  END sport2_o[10]
  PIN sport2_o[11]
    DIRECTION OUTPUT TRISTATE ;
    USE SIGNAL ;
    ANTENNADIFFAREA 0.795200 ;
    PORT
      LAYER met2 ;
        RECT 45.630 0.000 45.910 4.000 ;
    END
  END sport2_o[11]
  PIN sport2_o[12]
    DIRECTION OUTPUT TRISTATE ;
    USE SIGNAL ;
    ANTENNADIFFAREA 0.795200 ;
    PORT
      LAYER met2 ;
        RECT 47.010 0.000 47.290 4.000 ;
    END
  END sport2_o[12]
  PIN sport2_o[13]
    DIRECTION OUTPUT TRISTATE ;
    USE SIGNAL ;
    ANTENNADIFFAREA 0.795200 ;
    PORT
      LAYER met2 ;
        RECT 48.390 0.000 48.670 4.000 ;
    END
  END sport2_o[13]
  PIN sport2_o[14]
    DIRECTION OUTPUT TRISTATE ;
    USE SIGNAL ;
    ANTENNADIFFAREA 0.795200 ;
    PORT
      LAYER met2 ;
        RECT 49.770 0.000 50.050 4.000 ;
    END
  END sport2_o[14]
  PIN sport2_o[15]
    DIRECTION OUTPUT TRISTATE ;
    USE SIGNAL ;
    ANTENNADIFFAREA 0.795200 ;
    PORT
      LAYER met2 ;
        RECT 51.150 0.000 51.430 4.000 ;
    END
  END sport2_o[15]
  PIN sport2_o[16]
    DIRECTION OUTPUT TRISTATE ;
    USE SIGNAL ;
    ANTENNADIFFAREA 0.795200 ;
    PORT
      LAYER met2 ;
        RECT 52.530 0.000 52.810 4.000 ;
    END
  END sport2_o[16]
  PIN sport2_o[17]
    DIRECTION OUTPUT TRISTATE ;
    USE SIGNAL ;
    ANTENNADIFFAREA 0.795200 ;
    PORT
      LAYER met2 ;
        RECT 53.910 0.000 54.190 4.000 ;
    END
  END sport2_o[17]
  PIN sport2_o[18]
    DIRECTION OUTPUT TRISTATE ;
    USE SIGNAL ;
    ANTENNADIFFAREA 0.795200 ;
    PORT
      LAYER met2 ;
        RECT 55.290 0.000 55.570 4.000 ;
    END
  END sport2_o[18]
  PIN sport2_o[19]
    DIRECTION OUTPUT TRISTATE ;
    USE SIGNAL ;
    ANTENNADIFFAREA 0.795200 ;
    PORT
      LAYER met2 ;
        RECT 56.670 0.000 56.950 4.000 ;
    END
  END sport2_o[19]
  PIN sport2_o[1]
    DIRECTION OUTPUT TRISTATE ;
    USE SIGNAL ;
    ANTENNADIFFAREA 0.795200 ;
    PORT
      LAYER met2 ;
        RECT 31.830 0.000 32.110 4.000 ;
    END
  END sport2_o[1]
  PIN sport2_o[20]
    DIRECTION OUTPUT TRISTATE ;
    USE SIGNAL ;
    ANTENNADIFFAREA 0.795200 ;
    PORT
      LAYER met2 ;
        RECT 58.050 0.000 58.330 4.000 ;
    END
  END sport2_o[20]
  PIN sport2_o[21]
    DIRECTION OUTPUT TRISTATE ;
    USE SIGNAL ;
    ANTENNADIFFAREA 0.795200 ;
    PORT
      LAYER met2 ;
        RECT 59.430 0.000 59.710 4.000 ;
    END
  END sport2_o[21]
  PIN sport2_o[22]
    DIRECTION OUTPUT TRISTATE ;
    USE SIGNAL ;
    ANTENNADIFFAREA 0.795200 ;
    PORT
      LAYER met2 ;
        RECT 60.810 0.000 61.090 4.000 ;
    END
  END sport2_o[22]
  PIN sport2_o[23]
    DIRECTION OUTPUT TRISTATE ;
    USE SIGNAL ;
    ANTENNADIFFAREA 0.795200 ;
    PORT
      LAYER met2 ;
        RECT 62.190 0.000 62.470 4.000 ;
    END
  END sport2_o[23]
  PIN sport2_o[24]
    DIRECTION OUTPUT TRISTATE ;
    USE SIGNAL ;
    ANTENNADIFFAREA 0.795200 ;
    PORT
      LAYER met2 ;
        RECT 63.570 0.000 63.850 4.000 ;
    END
  END sport2_o[24]
  PIN sport2_o[25]
    DIRECTION OUTPUT TRISTATE ;
    USE SIGNAL ;
    ANTENNADIFFAREA 0.795200 ;
    PORT
      LAYER met2 ;
        RECT 64.950 0.000 65.230 4.000 ;
    END
  END sport2_o[25]
  PIN sport2_o[26]
    DIRECTION OUTPUT TRISTATE ;
    USE SIGNAL ;
    ANTENNADIFFAREA 0.795200 ;
    PORT
      LAYER met2 ;
        RECT 66.330 0.000 66.610 4.000 ;
    END
  END sport2_o[26]
  PIN sport2_o[27]
    DIRECTION OUTPUT TRISTATE ;
    USE SIGNAL ;
    ANTENNADIFFAREA 0.795200 ;
    PORT
      LAYER met2 ;
        RECT 67.710 0.000 67.990 4.000 ;
    END
  END sport2_o[27]
  PIN sport2_o[28]
    DIRECTION OUTPUT TRISTATE ;
    USE SIGNAL ;
    ANTENNADIFFAREA 0.795200 ;
    PORT
      LAYER met2 ;
        RECT 69.090 0.000 69.370 4.000 ;
    END
  END sport2_o[28]
  PIN sport2_o[29]
    DIRECTION OUTPUT TRISTATE ;
    USE SIGNAL ;
    ANTENNADIFFAREA 0.795200 ;
    PORT
      LAYER met2 ;
        RECT 70.470 0.000 70.750 4.000 ;
    END
  END sport2_o[29]
  PIN sport2_o[2]
    DIRECTION OUTPUT TRISTATE ;
    USE SIGNAL ;
    ANTENNADIFFAREA 0.795200 ;
    PORT
      LAYER met2 ;
        RECT 33.210 0.000 33.490 4.000 ;
    END
  END sport2_o[2]
  PIN sport2_o[30]
    DIRECTION OUTPUT TRISTATE ;
    USE SIGNAL ;
    ANTENNADIFFAREA 0.795200 ;
    PORT
      LAYER met2 ;
        RECT 71.850 0.000 72.130 4.000 ;
    END
  END sport2_o[30]
  PIN sport2_o[31]
    DIRECTION OUTPUT TRISTATE ;
    USE SIGNAL ;
    ANTENNADIFFAREA 0.795200 ;
    PORT
      LAYER met2 ;
        RECT 73.230 0.000 73.510 4.000 ;
    END
  END sport2_o[31]
  PIN sport2_o[32]
    DIRECTION OUTPUT TRISTATE ;
    USE SIGNAL ;
    ANTENNADIFFAREA 0.795200 ;
    PORT
      LAYER met2 ;
        RECT 74.610 0.000 74.890 4.000 ;
    END
  END sport2_o[32]
  PIN sport2_o[33]
    DIRECTION OUTPUT TRISTATE ;
    USE SIGNAL ;
    ANTENNADIFFAREA 0.795200 ;
    PORT
      LAYER met2 ;
        RECT 75.990 0.000 76.270 4.000 ;
    END
  END sport2_o[33]
  PIN sport2_o[3]
    DIRECTION OUTPUT TRISTATE ;
    USE SIGNAL ;
    ANTENNADIFFAREA 0.795200 ;
    PORT
      LAYER met2 ;
        RECT 34.590 0.000 34.870 4.000 ;
    END
  END sport2_o[3]
  PIN sport2_o[4]
    DIRECTION OUTPUT TRISTATE ;
    USE SIGNAL ;
    ANTENNADIFFAREA 0.795200 ;
    PORT
      LAYER met2 ;
        RECT 35.970 0.000 36.250 4.000 ;
    END
  END sport2_o[4]
  PIN sport2_o[5]
    DIRECTION OUTPUT TRISTATE ;
    USE SIGNAL ;
    ANTENNADIFFAREA 0.795200 ;
    PORT
      LAYER met2 ;
        RECT 37.350 0.000 37.630 4.000 ;
    END
  END sport2_o[5]
  PIN sport2_o[6]
    DIRECTION OUTPUT TRISTATE ;
    USE SIGNAL ;
    ANTENNADIFFAREA 0.795200 ;
    PORT
      LAYER met2 ;
        RECT 38.730 0.000 39.010 4.000 ;
    END
  END sport2_o[6]
  PIN sport2_o[7]
    DIRECTION OUTPUT TRISTATE ;
    USE SIGNAL ;
    ANTENNADIFFAREA 0.795200 ;
    PORT
      LAYER met2 ;
        RECT 40.110 0.000 40.390 4.000 ;
    END
  END sport2_o[7]
  PIN sport2_o[8]
    DIRECTION OUTPUT TRISTATE ;
    USE SIGNAL ;
    ANTENNADIFFAREA 0.795200 ;
    PORT
      LAYER met2 ;
        RECT 41.490 0.000 41.770 4.000 ;
    END
  END sport2_o[8]
  PIN sport2_o[9]
    DIRECTION OUTPUT TRISTATE ;
    USE SIGNAL ;
    ANTENNADIFFAREA 0.795200 ;
    PORT
      LAYER met2 ;
        RECT 42.870 0.000 43.150 4.000 ;
    END
  END sport2_o[9]
  PIN vccd1
    DIRECTION INOUT ;
    USE POWER ;
    PORT
      LAYER met4 ;
        RECT 21.040 10.640 22.640 236.880 ;
    END
    PORT
      LAYER met4 ;
        RECT 174.640 10.640 176.240 236.880 ;
    END
  END vccd1
  PIN vssd1
    DIRECTION INOUT ;
    USE GROUND ;
    PORT
      LAYER met4 ;
        RECT 97.840 10.640 99.440 236.880 ;
    END
  END vssd1
  OBS
      LAYER nwell ;
        RECT 5.330 235.225 194.310 236.830 ;
        RECT 5.330 229.785 194.310 232.615 ;
        RECT 5.330 224.345 194.310 227.175 ;
        RECT 5.330 218.905 194.310 221.735 ;
        RECT 5.330 213.465 194.310 216.295 ;
        RECT 5.330 208.025 194.310 210.855 ;
        RECT 5.330 202.585 194.310 205.415 ;
        RECT 5.330 197.145 194.310 199.975 ;
        RECT 5.330 191.705 194.310 194.535 ;
        RECT 5.330 186.265 194.310 189.095 ;
        RECT 5.330 180.825 194.310 183.655 ;
        RECT 5.330 175.385 194.310 178.215 ;
        RECT 5.330 169.945 194.310 172.775 ;
        RECT 5.330 164.505 194.310 167.335 ;
        RECT 5.330 159.065 194.310 161.895 ;
        RECT 5.330 153.625 194.310 156.455 ;
        RECT 5.330 148.185 194.310 151.015 ;
        RECT 5.330 142.745 194.310 145.575 ;
        RECT 5.330 137.305 194.310 140.135 ;
        RECT 5.330 131.865 194.310 134.695 ;
        RECT 5.330 126.425 194.310 129.255 ;
        RECT 5.330 120.985 194.310 123.815 ;
        RECT 5.330 115.545 194.310 118.375 ;
        RECT 5.330 110.105 194.310 112.935 ;
        RECT 5.330 104.665 194.310 107.495 ;
        RECT 5.330 99.225 194.310 102.055 ;
        RECT 5.330 93.785 194.310 96.615 ;
        RECT 5.330 88.345 194.310 91.175 ;
        RECT 5.330 82.905 194.310 85.735 ;
        RECT 5.330 77.465 194.310 80.295 ;
        RECT 5.330 72.025 194.310 74.855 ;
        RECT 5.330 66.585 194.310 69.415 ;
        RECT 5.330 61.145 194.310 63.975 ;
        RECT 5.330 55.705 194.310 58.535 ;
        RECT 5.330 50.265 194.310 53.095 ;
        RECT 5.330 44.825 194.310 47.655 ;
        RECT 5.330 39.385 194.310 42.215 ;
        RECT 5.330 33.945 194.310 36.775 ;
        RECT 5.330 28.505 194.310 31.335 ;
        RECT 5.330 23.065 194.310 25.895 ;
        RECT 5.330 17.625 194.310 20.455 ;
        RECT 5.330 12.185 194.310 15.015 ;
      LAYER li1 ;
        RECT 5.520 10.795 194.120 236.725 ;
      LAYER met1 ;
        RECT 5.520 1.060 194.510 237.960 ;
      LAYER met2 ;
        RECT 6.080 245.720 7.630 246.570 ;
        RECT 8.470 245.720 11.310 246.570 ;
        RECT 12.150 245.720 14.990 246.570 ;
        RECT 15.830 245.720 18.670 246.570 ;
        RECT 19.510 245.720 22.350 246.570 ;
        RECT 23.190 245.720 26.030 246.570 ;
        RECT 26.870 245.720 29.710 246.570 ;
        RECT 30.550 245.720 33.390 246.570 ;
        RECT 34.230 245.720 37.070 246.570 ;
        RECT 37.910 245.720 40.750 246.570 ;
        RECT 41.590 245.720 44.430 246.570 ;
        RECT 45.270 245.720 48.110 246.570 ;
        RECT 48.950 245.720 51.790 246.570 ;
        RECT 52.630 245.720 55.470 246.570 ;
        RECT 56.310 245.720 59.150 246.570 ;
        RECT 59.990 245.720 62.830 246.570 ;
        RECT 63.670 245.720 66.510 246.570 ;
        RECT 67.350 245.720 70.190 246.570 ;
        RECT 71.030 245.720 73.870 246.570 ;
        RECT 74.710 245.720 77.550 246.570 ;
        RECT 78.390 245.720 81.230 246.570 ;
        RECT 82.070 245.720 84.910 246.570 ;
        RECT 85.750 245.720 88.590 246.570 ;
        RECT 89.430 245.720 92.270 246.570 ;
        RECT 93.110 245.720 95.950 246.570 ;
        RECT 96.790 245.720 99.630 246.570 ;
        RECT 100.470 245.720 103.310 246.570 ;
        RECT 104.150 245.720 106.990 246.570 ;
        RECT 107.830 245.720 110.670 246.570 ;
        RECT 111.510 245.720 114.350 246.570 ;
        RECT 115.190 245.720 118.030 246.570 ;
        RECT 118.870 245.720 121.710 246.570 ;
        RECT 122.550 245.720 125.390 246.570 ;
        RECT 126.230 245.720 129.070 246.570 ;
        RECT 129.910 245.720 132.750 246.570 ;
        RECT 133.590 245.720 136.430 246.570 ;
        RECT 137.270 245.720 140.110 246.570 ;
        RECT 140.950 245.720 143.790 246.570 ;
        RECT 144.630 245.720 147.470 246.570 ;
        RECT 148.310 245.720 151.150 246.570 ;
        RECT 151.990 245.720 154.830 246.570 ;
        RECT 155.670 245.720 158.510 246.570 ;
        RECT 159.350 245.720 162.190 246.570 ;
        RECT 163.030 245.720 165.870 246.570 ;
        RECT 166.710 245.720 169.550 246.570 ;
        RECT 170.390 245.720 173.230 246.570 ;
        RECT 174.070 245.720 176.910 246.570 ;
        RECT 177.750 245.720 180.590 246.570 ;
        RECT 181.430 245.720 184.270 246.570 ;
        RECT 185.110 245.720 187.950 246.570 ;
        RECT 188.790 245.720 191.630 246.570 ;
        RECT 192.470 245.720 194.480 246.570 ;
        RECT 6.080 4.280 194.480 245.720 ;
        RECT 6.080 0.835 28.330 4.280 ;
        RECT 171.770 0.835 194.480 4.280 ;
      LAYER met3 ;
        RECT 9.265 0.180 193.595 236.805 ;
      LAYER met4 ;
        RECT 15.935 10.240 20.640 214.705 ;
        RECT 23.040 10.240 97.440 214.705 ;
        RECT 99.840 10.240 174.240 214.705 ;
        RECT 176.640 10.240 188.305 214.705 ;
        RECT 15.935 0.175 188.305 10.240 ;
  END
END spi_block_m
END LIBRARY

